VERSION 5.8 ;
BUSBITCHARS "[]" ;
DIVIDERCHAR "/" ;
UNITS
    DATABASE MICRONS 1000 ;
END UNITS

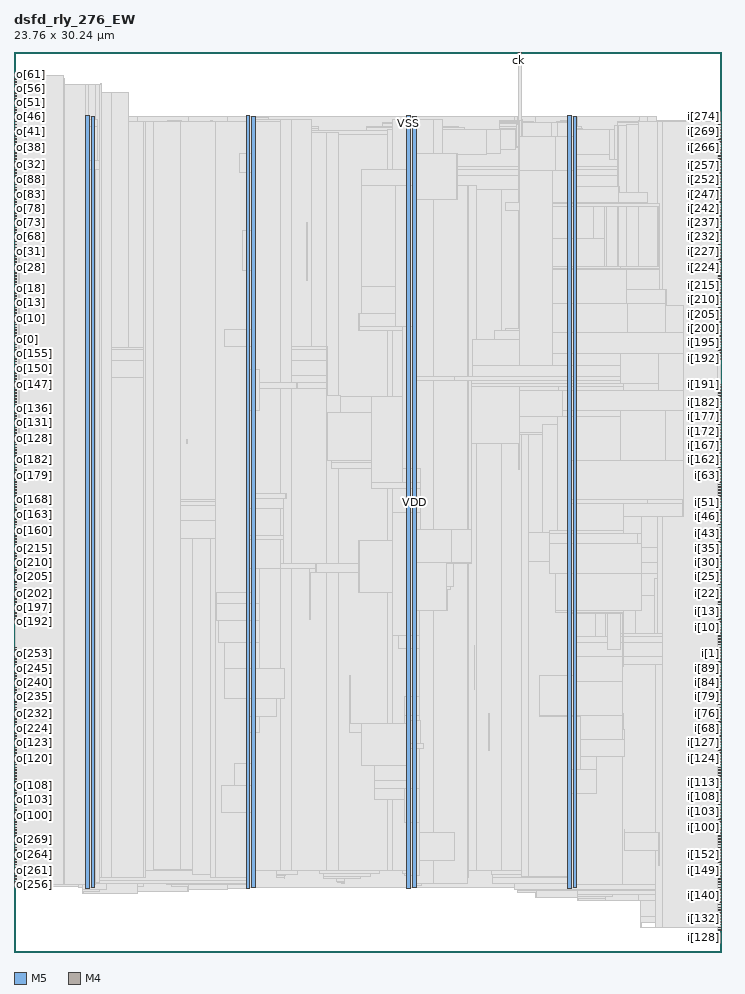
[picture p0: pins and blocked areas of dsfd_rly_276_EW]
MACRO dsfd_rly_276_EW
  FOREIGN dsfd_rly_276_EW 0 0 ;
  CLASS BLOCK ;
  SIZE 23.76 BY 30.24 ;
  PIN ck
    DIRECTION INPUT ;
    USE SIGNAL ;
    PORT
      LAYER M5 ;
        RECT  16.944 30.156 16.968 30.24 ;
    END
  END ck
  PIN i[0]
    DIRECTION INPUT ;
    USE SIGNAL ;
    PORT
      LAYER M4 ;
        RECT  23.676 9.936 23.76 9.96 ;
    END
  END i[0]
  PIN i[100]
    DIRECTION INPUT ;
    USE SIGNAL ;
    PORT
      LAYER M4 ;
        RECT  23.676 4.176 23.76 4.2 ;
    END
  END i[100]
  PIN i[101]
    DIRECTION INPUT ;
    USE SIGNAL ;
    PORT
      LAYER M4 ;
        RECT  23.676 4.272 23.76 4.296 ;
    END
  END i[101]
  PIN i[102]
    DIRECTION INPUT ;
    USE SIGNAL ;
    PORT
      LAYER M4 ;
        RECT  23.676 4.368 23.76 4.392 ;
    END
  END i[102]
  PIN i[103]
    DIRECTION INPUT ;
    USE SIGNAL ;
    PORT
      LAYER M4 ;
        RECT  23.676 4.464 23.76 4.488 ;
    END
  END i[103]
  PIN i[104]
    DIRECTION INPUT ;
    USE SIGNAL ;
    PORT
      LAYER M4 ;
        RECT  23.676 4.56 23.76 4.584 ;
    END
  END i[104]
  PIN i[105]
    DIRECTION INPUT ;
    USE SIGNAL ;
    PORT
      LAYER M4 ;
        RECT  23.676 4.656 23.76 4.68 ;
    END
  END i[105]
  PIN i[106]
    DIRECTION INPUT ;
    USE SIGNAL ;
    PORT
      LAYER M4 ;
        RECT  23.676 4.752 23.76 4.776 ;
    END
  END i[106]
  PIN i[107]
    DIRECTION INPUT ;
    USE SIGNAL ;
    PORT
      LAYER M4 ;
        RECT  23.676 4.848 23.76 4.872 ;
    END
  END i[107]
  PIN i[108]
    DIRECTION INPUT ;
    USE SIGNAL ;
    PORT
      LAYER M4 ;
        RECT  23.676 4.944 23.76 4.968 ;
    END
  END i[108]
  PIN i[109]
    DIRECTION INPUT ;
    USE SIGNAL ;
    PORT
      LAYER M4 ;
        RECT  23.676 5.04 23.76 5.064 ;
    END
  END i[109]
  PIN i[10]
    DIRECTION INPUT ;
    USE SIGNAL ;
    PORT
      LAYER M4 ;
        RECT  23.676 10.896 23.76 10.92 ;
    END
  END i[10]
  PIN i[110]
    DIRECTION INPUT ;
    USE SIGNAL ;
    PORT
      LAYER M4 ;
        RECT  23.676 5.136 23.76 5.16 ;
    END
  END i[110]
  PIN i[111]
    DIRECTION INPUT ;
    USE SIGNAL ;
    PORT
      LAYER M4 ;
        RECT  23.676 5.232 23.76 5.256 ;
    END
  END i[111]
  PIN i[112]
    DIRECTION INPUT ;
    USE SIGNAL ;
    PORT
      LAYER M4 ;
        RECT  23.676 5.328 23.76 5.352 ;
    END
  END i[112]
  PIN i[113]
    DIRECTION INPUT ;
    USE SIGNAL ;
    PORT
      LAYER M4 ;
        RECT  23.676 5.424 23.76 5.448 ;
    END
  END i[113]
  PIN i[114]
    DIRECTION INPUT ;
    USE SIGNAL ;
    PORT
      LAYER M4 ;
        RECT  23.676 5.52 23.76 5.544 ;
    END
  END i[114]
  PIN i[115]
    DIRECTION INPUT ;
    USE SIGNAL ;
    PORT
      LAYER M4 ;
        RECT  23.676 5.616 23.76 5.64 ;
    END
  END i[115]
  PIN i[116]
    DIRECTION INPUT ;
    USE SIGNAL ;
    PORT
      LAYER M4 ;
        RECT  23.676 5.712 23.76 5.736 ;
    END
  END i[116]
  PIN i[117]
    DIRECTION INPUT ;
    USE SIGNAL ;
    PORT
      LAYER M4 ;
        RECT  23.676 5.808 23.76 5.832 ;
    END
  END i[117]
  PIN i[118]
    DIRECTION INPUT ;
    USE SIGNAL ;
    PORT
      LAYER M4 ;
        RECT  23.676 5.904 23.76 5.928 ;
    END
  END i[118]
  PIN i[119]
    DIRECTION INPUT ;
    USE SIGNAL ;
    PORT
      LAYER M4 ;
        RECT  23.676 6 23.76 6.024 ;
    END
  END i[119]
  PIN i[11]
    DIRECTION INPUT ;
    USE SIGNAL ;
    PORT
      LAYER M4 ;
        RECT  23.676 10.992 23.76 11.016 ;
    END
  END i[11]
  PIN i[120]
    DIRECTION INPUT ;
    USE SIGNAL ;
    PORT
      LAYER M4 ;
        RECT  23.676 6.096 23.76 6.12 ;
    END
  END i[120]
  PIN i[121]
    DIRECTION INPUT ;
    USE SIGNAL ;
    PORT
      LAYER M4 ;
        RECT  23.676 6.192 23.76 6.216 ;
    END
  END i[121]
  PIN i[122]
    DIRECTION INPUT ;
    USE SIGNAL ;
    PORT
      LAYER M4 ;
        RECT  23.676 6.288 23.76 6.312 ;
    END
  END i[122]
  PIN i[123]
    DIRECTION INPUT ;
    USE SIGNAL ;
    PORT
      LAYER M4 ;
        RECT  23.676 6.384 23.76 6.408 ;
    END
  END i[123]
  PIN i[124]
    DIRECTION INPUT ;
    USE SIGNAL ;
    PORT
      LAYER M4 ;
        RECT  23.676 6.48 23.76 6.504 ;
    END
  END i[124]
  PIN i[125]
    DIRECTION INPUT ;
    USE SIGNAL ;
    PORT
      LAYER M4 ;
        RECT  23.676 6.576 23.76 6.6 ;
    END
  END i[125]
  PIN i[126]
    DIRECTION INPUT ;
    USE SIGNAL ;
    PORT
      LAYER M4 ;
        RECT  23.676 6.672 23.76 6.696 ;
    END
  END i[126]
  PIN i[127]
    DIRECTION INPUT ;
    USE SIGNAL ;
    PORT
      LAYER M4 ;
        RECT  23.676 6.768 23.76 6.792 ;
    END
  END i[127]
  PIN i[128]
    DIRECTION INPUT ;
    USE SIGNAL ;
    PORT
      LAYER M4 ;
        RECT  23.676 0.72 23.76 0.744 ;
    END
  END i[128]
  PIN i[129]
    DIRECTION INPUT ;
    USE SIGNAL ;
    PORT
      LAYER M4 ;
        RECT  23.676 0.816 23.76 0.84 ;
    END
  END i[129]
  PIN i[12]
    DIRECTION INPUT ;
    USE SIGNAL ;
    PORT
      LAYER M4 ;
        RECT  23.676 11.088 23.76 11.112 ;
    END
  END i[12]
  PIN i[130]
    DIRECTION INPUT ;
    USE SIGNAL ;
    PORT
      LAYER M4 ;
        RECT  23.676 0.912 23.76 0.936 ;
    END
  END i[130]
  PIN i[131]
    DIRECTION INPUT ;
    USE SIGNAL ;
    PORT
      LAYER M4 ;
        RECT  23.676 1.008 23.76 1.032 ;
    END
  END i[131]
  PIN i[132]
    DIRECTION INPUT ;
    USE SIGNAL ;
    PORT
      LAYER M4 ;
        RECT  23.676 1.104 23.76 1.128 ;
    END
  END i[132]
  PIN i[133]
    DIRECTION INPUT ;
    USE SIGNAL ;
    PORT
      LAYER M4 ;
        RECT  23.676 1.2 23.76 1.224 ;
    END
  END i[133]
  PIN i[134]
    DIRECTION INPUT ;
    USE SIGNAL ;
    PORT
      LAYER M4 ;
        RECT  23.676 1.296 23.76 1.32 ;
    END
  END i[134]
  PIN i[135]
    DIRECTION INPUT ;
    USE SIGNAL ;
    PORT
      LAYER M4 ;
        RECT  23.676 1.392 23.76 1.416 ;
    END
  END i[135]
  PIN i[136]
    DIRECTION INPUT ;
    USE SIGNAL ;
    PORT
      LAYER M4 ;
        RECT  23.676 1.488 23.76 1.512 ;
    END
  END i[136]
  PIN i[137]
    DIRECTION INPUT ;
    USE SIGNAL ;
    PORT
      LAYER M4 ;
        RECT  23.676 1.584 23.76 1.608 ;
    END
  END i[137]
  PIN i[138]
    DIRECTION INPUT ;
    USE SIGNAL ;
    PORT
      LAYER M4 ;
        RECT  23.676 1.68 23.76 1.704 ;
    END
  END i[138]
  PIN i[139]
    DIRECTION INPUT ;
    USE SIGNAL ;
    PORT
      LAYER M4 ;
        RECT  23.676 1.776 23.76 1.8 ;
    END
  END i[139]
  PIN i[13]
    DIRECTION INPUT ;
    USE SIGNAL ;
    PORT
      LAYER M4 ;
        RECT  23.676 11.184 23.76 11.208 ;
    END
  END i[13]
  PIN i[140]
    DIRECTION INPUT ;
    USE SIGNAL ;
    PORT
      LAYER M4 ;
        RECT  23.676 1.872 23.76 1.896 ;
    END
  END i[140]
  PIN i[141]
    DIRECTION INPUT ;
    USE SIGNAL ;
    PORT
      LAYER M4 ;
        RECT  23.676 1.968 23.76 1.992 ;
    END
  END i[141]
  PIN i[142]
    DIRECTION INPUT ;
    USE SIGNAL ;
    PORT
      LAYER M4 ;
        RECT  23.676 2.064 23.76 2.088 ;
    END
  END i[142]
  PIN i[143]
    DIRECTION INPUT ;
    USE SIGNAL ;
    PORT
      LAYER M4 ;
        RECT  23.676 2.16 23.76 2.184 ;
    END
  END i[143]
  PIN i[144]
    DIRECTION INPUT ;
    USE SIGNAL ;
    PORT
      LAYER M4 ;
        RECT  23.676 2.256 23.76 2.28 ;
    END
  END i[144]
  PIN i[145]
    DIRECTION INPUT ;
    USE SIGNAL ;
    PORT
      LAYER M4 ;
        RECT  23.676 2.352 23.76 2.376 ;
    END
  END i[145]
  PIN i[146]
    DIRECTION INPUT ;
    USE SIGNAL ;
    PORT
      LAYER M4 ;
        RECT  23.676 2.448 23.76 2.472 ;
    END
  END i[146]
  PIN i[147]
    DIRECTION INPUT ;
    USE SIGNAL ;
    PORT
      LAYER M4 ;
        RECT  23.676 2.544 23.76 2.568 ;
    END
  END i[147]
  PIN i[148]
    DIRECTION INPUT ;
    USE SIGNAL ;
    PORT
      LAYER M4 ;
        RECT  23.676 2.64 23.76 2.664 ;
    END
  END i[148]
  PIN i[149]
    DIRECTION INPUT ;
    USE SIGNAL ;
    PORT
      LAYER M4 ;
        RECT  23.676 2.736 23.76 2.76 ;
    END
  END i[149]
  PIN i[14]
    DIRECTION INPUT ;
    USE SIGNAL ;
    PORT
      LAYER M4 ;
        RECT  23.676 11.28 23.76 11.304 ;
    END
  END i[14]
  PIN i[150]
    DIRECTION INPUT ;
    USE SIGNAL ;
    PORT
      LAYER M4 ;
        RECT  23.676 2.832 23.76 2.856 ;
    END
  END i[150]
  PIN i[151]
    DIRECTION INPUT ;
    USE SIGNAL ;
    PORT
      LAYER M4 ;
        RECT  23.676 2.928 23.76 2.952 ;
    END
  END i[151]
  PIN i[152]
    DIRECTION INPUT ;
    USE SIGNAL ;
    PORT
      LAYER M4 ;
        RECT  23.676 3.024 23.76 3.048 ;
    END
  END i[152]
  PIN i[153]
    DIRECTION INPUT ;
    USE SIGNAL ;
    PORT
      LAYER M4 ;
        RECT  23.676 3.12 23.76 3.144 ;
    END
  END i[153]
  PIN i[154]
    DIRECTION INPUT ;
    USE SIGNAL ;
    PORT
      LAYER M4 ;
        RECT  23.676 3.216 23.76 3.24 ;
    END
  END i[154]
  PIN i[155]
    DIRECTION INPUT ;
    USE SIGNAL ;
    PORT
      LAYER M4 ;
        RECT  23.676 3.312 23.76 3.336 ;
    END
  END i[155]
  PIN i[156]
    DIRECTION INPUT ;
    USE SIGNAL ;
    PORT
      LAYER M4 ;
        RECT  23.676 3.408 23.76 3.432 ;
    END
  END i[156]
  PIN i[157]
    DIRECTION INPUT ;
    USE SIGNAL ;
    PORT
      LAYER M4 ;
        RECT  23.676 3.504 23.76 3.528 ;
    END
  END i[157]
  PIN i[158]
    DIRECTION INPUT ;
    USE SIGNAL ;
    PORT
      LAYER M4 ;
        RECT  23.676 3.6 23.76 3.624 ;
    END
  END i[158]
  PIN i[159]
    DIRECTION INPUT ;
    USE SIGNAL ;
    PORT
      LAYER M4 ;
        RECT  23.676 3.696 23.76 3.72 ;
    END
  END i[159]
  PIN i[15]
    DIRECTION INPUT ;
    USE SIGNAL ;
    PORT
      LAYER M4 ;
        RECT  23.676 11.376 23.76 11.4 ;
    END
  END i[15]
  PIN i[160]
    DIRECTION INPUT ;
    USE SIGNAL ;
    PORT
      LAYER M4 ;
        RECT  23.676 16.08 23.76 16.104 ;
    END
  END i[160]
  PIN i[161]
    DIRECTION INPUT ;
    USE SIGNAL ;
    PORT
      LAYER M4 ;
        RECT  23.676 16.176 23.76 16.2 ;
    END
  END i[161]
  PIN i[162]
    DIRECTION INPUT ;
    USE SIGNAL ;
    PORT
      LAYER M4 ;
        RECT  23.676 16.272 23.76 16.296 ;
    END
  END i[162]
  PIN i[163]
    DIRECTION INPUT ;
    USE SIGNAL ;
    PORT
      LAYER M4 ;
        RECT  23.676 16.368 23.76 16.392 ;
    END
  END i[163]
  PIN i[164]
    DIRECTION INPUT ;
    USE SIGNAL ;
    PORT
      LAYER M4 ;
        RECT  23.676 16.464 23.76 16.488 ;
    END
  END i[164]
  PIN i[165]
    DIRECTION INPUT ;
    USE SIGNAL ;
    PORT
      LAYER M4 ;
        RECT  23.676 16.56 23.76 16.584 ;
    END
  END i[165]
  PIN i[166]
    DIRECTION INPUT ;
    USE SIGNAL ;
    PORT
      LAYER M4 ;
        RECT  23.676 16.656 23.76 16.68 ;
    END
  END i[166]
  PIN i[167]
    DIRECTION INPUT ;
    USE SIGNAL ;
    PORT
      LAYER M4 ;
        RECT  23.676 16.752 23.76 16.776 ;
    END
  END i[167]
  PIN i[168]
    DIRECTION INPUT ;
    USE SIGNAL ;
    PORT
      LAYER M4 ;
        RECT  23.676 16.848 23.76 16.872 ;
    END
  END i[168]
  PIN i[169]
    DIRECTION INPUT ;
    USE SIGNAL ;
    PORT
      LAYER M4 ;
        RECT  23.676 16.944 23.76 16.968 ;
    END
  END i[169]
  PIN i[16]
    DIRECTION INPUT ;
    USE SIGNAL ;
    PORT
      LAYER M4 ;
        RECT  23.676 11.472 23.76 11.496 ;
    END
  END i[16]
  PIN i[170]
    DIRECTION INPUT ;
    USE SIGNAL ;
    PORT
      LAYER M4 ;
        RECT  23.676 17.04 23.76 17.064 ;
    END
  END i[170]
  PIN i[171]
    DIRECTION INPUT ;
    USE SIGNAL ;
    PORT
      LAYER M4 ;
        RECT  23.676 17.136 23.76 17.16 ;
    END
  END i[171]
  PIN i[172]
    DIRECTION INPUT ;
    USE SIGNAL ;
    PORT
      LAYER M4 ;
        RECT  23.676 17.232 23.76 17.256 ;
    END
  END i[172]
  PIN i[173]
    DIRECTION INPUT ;
    USE SIGNAL ;
    PORT
      LAYER M4 ;
        RECT  23.676 17.328 23.76 17.352 ;
    END
  END i[173]
  PIN i[174]
    DIRECTION INPUT ;
    USE SIGNAL ;
    PORT
      LAYER M4 ;
        RECT  23.676 17.424 23.76 17.448 ;
    END
  END i[174]
  PIN i[175]
    DIRECTION INPUT ;
    USE SIGNAL ;
    PORT
      LAYER M4 ;
        RECT  23.676 17.52 23.76 17.544 ;
    END
  END i[175]
  PIN i[176]
    DIRECTION INPUT ;
    USE SIGNAL ;
    PORT
      LAYER M4 ;
        RECT  23.676 17.616 23.76 17.64 ;
    END
  END i[176]
  PIN i[177]
    DIRECTION INPUT ;
    USE SIGNAL ;
    PORT
      LAYER M4 ;
        RECT  23.676 17.712 23.76 17.736 ;
    END
  END i[177]
  PIN i[178]
    DIRECTION INPUT ;
    USE SIGNAL ;
    PORT
      LAYER M4 ;
        RECT  23.676 17.808 23.76 17.832 ;
    END
  END i[178]
  PIN i[179]
    DIRECTION INPUT ;
    USE SIGNAL ;
    PORT
      LAYER M4 ;
        RECT  23.676 17.904 23.76 17.928 ;
    END
  END i[179]
  PIN i[17]
    DIRECTION INPUT ;
    USE SIGNAL ;
    PORT
      LAYER M4 ;
        RECT  23.676 11.568 23.76 11.592 ;
    END
  END i[17]
  PIN i[180]
    DIRECTION INPUT ;
    USE SIGNAL ;
    PORT
      LAYER M4 ;
        RECT  23.676 18 23.76 18.024 ;
    END
  END i[180]
  PIN i[181]
    DIRECTION INPUT ;
    USE SIGNAL ;
    PORT
      LAYER M4 ;
        RECT  23.676 18.096 23.76 18.12 ;
    END
  END i[181]
  PIN i[182]
    DIRECTION INPUT ;
    USE SIGNAL ;
    PORT
      LAYER M4 ;
        RECT  23.676 18.192 23.76 18.216 ;
    END
  END i[182]
  PIN i[183]
    DIRECTION INPUT ;
    USE SIGNAL ;
    PORT
      LAYER M4 ;
        RECT  23.676 18.288 23.76 18.312 ;
    END
  END i[183]
  PIN i[184]
    DIRECTION INPUT ;
    USE SIGNAL ;
    PORT
      LAYER M4 ;
        RECT  23.676 18.384 23.76 18.408 ;
    END
  END i[184]
  PIN i[185]
    DIRECTION INPUT ;
    USE SIGNAL ;
    PORT
      LAYER M4 ;
        RECT  23.676 18.48 23.76 18.504 ;
    END
  END i[185]
  PIN i[186]
    DIRECTION INPUT ;
    USE SIGNAL ;
    PORT
      LAYER M4 ;
        RECT  23.676 18.576 23.76 18.6 ;
    END
  END i[186]
  PIN i[187]
    DIRECTION INPUT ;
    USE SIGNAL ;
    PORT
      LAYER M4 ;
        RECT  23.676 18.672 23.76 18.696 ;
    END
  END i[187]
  PIN i[188]
    DIRECTION INPUT ;
    USE SIGNAL ;
    PORT
      LAYER M4 ;
        RECT  23.676 18.768 23.76 18.792 ;
    END
  END i[188]
  PIN i[189]
    DIRECTION INPUT ;
    USE SIGNAL ;
    PORT
      LAYER M4 ;
        RECT  23.676 18.864 23.76 18.888 ;
    END
  END i[189]
  PIN i[18]
    DIRECTION INPUT ;
    USE SIGNAL ;
    PORT
      LAYER M4 ;
        RECT  23.676 11.664 23.76 11.688 ;
    END
  END i[18]
  PIN i[190]
    DIRECTION INPUT ;
    USE SIGNAL ;
    PORT
      LAYER M4 ;
        RECT  23.676 18.96 23.76 18.984 ;
    END
  END i[190]
  PIN i[191]
    DIRECTION INPUT ;
    USE SIGNAL ;
    PORT
      LAYER M4 ;
        RECT  23.676 19.056 23.76 19.08 ;
    END
  END i[191]
  PIN i[192]
    DIRECTION INPUT ;
    USE SIGNAL ;
    PORT
      LAYER M4 ;
        RECT  23.676 19.92 23.76 19.944 ;
    END
  END i[192]
  PIN i[193]
    DIRECTION INPUT ;
    USE SIGNAL ;
    PORT
      LAYER M4 ;
        RECT  23.676 20.016 23.76 20.04 ;
    END
  END i[193]
  PIN i[194]
    DIRECTION INPUT ;
    USE SIGNAL ;
    PORT
      LAYER M4 ;
        RECT  23.676 20.112 23.76 20.136 ;
    END
  END i[194]
  PIN i[195]
    DIRECTION INPUT ;
    USE SIGNAL ;
    PORT
      LAYER M4 ;
        RECT  23.676 20.208 23.76 20.232 ;
    END
  END i[195]
  PIN i[196]
    DIRECTION INPUT ;
    USE SIGNAL ;
    PORT
      LAYER M4 ;
        RECT  23.676 20.304 23.76 20.328 ;
    END
  END i[196]
  PIN i[197]
    DIRECTION INPUT ;
    USE SIGNAL ;
    PORT
      LAYER M4 ;
        RECT  23.676 20.4 23.76 20.424 ;
    END
  END i[197]
  PIN i[198]
    DIRECTION INPUT ;
    USE SIGNAL ;
    PORT
      LAYER M4 ;
        RECT  23.676 20.496 23.76 20.52 ;
    END
  END i[198]
  PIN i[199]
    DIRECTION INPUT ;
    USE SIGNAL ;
    PORT
      LAYER M4 ;
        RECT  23.676 20.592 23.76 20.616 ;
    END
  END i[199]
  PIN i[19]
    DIRECTION INPUT ;
    USE SIGNAL ;
    PORT
      LAYER M4 ;
        RECT  23.676 11.76 23.76 11.784 ;
    END
  END i[19]
  PIN i[1]
    DIRECTION INPUT ;
    USE SIGNAL ;
    PORT
      LAYER M4 ;
        RECT  23.676 10.032 23.76 10.056 ;
    END
  END i[1]
  PIN i[200]
    DIRECTION INPUT ;
    USE SIGNAL ;
    PORT
      LAYER M4 ;
        RECT  23.676 20.688 23.76 20.712 ;
    END
  END i[200]
  PIN i[201]
    DIRECTION INPUT ;
    USE SIGNAL ;
    PORT
      LAYER M4 ;
        RECT  23.676 20.784 23.76 20.808 ;
    END
  END i[201]
  PIN i[202]
    DIRECTION INPUT ;
    USE SIGNAL ;
    PORT
      LAYER M4 ;
        RECT  23.676 20.88 23.76 20.904 ;
    END
  END i[202]
  PIN i[203]
    DIRECTION INPUT ;
    USE SIGNAL ;
    PORT
      LAYER M4 ;
        RECT  23.676 20.976 23.76 21 ;
    END
  END i[203]
  PIN i[204]
    DIRECTION INPUT ;
    USE SIGNAL ;
    PORT
      LAYER M4 ;
        RECT  23.676 21.072 23.76 21.096 ;
    END
  END i[204]
  PIN i[205]
    DIRECTION INPUT ;
    USE SIGNAL ;
    PORT
      LAYER M4 ;
        RECT  23.676 21.168 23.76 21.192 ;
    END
  END i[205]
  PIN i[206]
    DIRECTION INPUT ;
    USE SIGNAL ;
    PORT
      LAYER M4 ;
        RECT  23.676 21.264 23.76 21.288 ;
    END
  END i[206]
  PIN i[207]
    DIRECTION INPUT ;
    USE SIGNAL ;
    PORT
      LAYER M4 ;
        RECT  23.676 21.36 23.76 21.384 ;
    END
  END i[207]
  PIN i[208]
    DIRECTION INPUT ;
    USE SIGNAL ;
    PORT
      LAYER M4 ;
        RECT  23.676 21.456 23.76 21.48 ;
    END
  END i[208]
  PIN i[209]
    DIRECTION INPUT ;
    USE SIGNAL ;
    PORT
      LAYER M4 ;
        RECT  23.676 21.552 23.76 21.576 ;
    END
  END i[209]
  PIN i[20]
    DIRECTION INPUT ;
    USE SIGNAL ;
    PORT
      LAYER M4 ;
        RECT  23.676 11.856 23.76 11.88 ;
    END
  END i[20]
  PIN i[210]
    DIRECTION INPUT ;
    USE SIGNAL ;
    PORT
      LAYER M4 ;
        RECT  23.676 21.648 23.76 21.672 ;
    END
  END i[210]
  PIN i[211]
    DIRECTION INPUT ;
    USE SIGNAL ;
    PORT
      LAYER M4 ;
        RECT  23.676 21.744 23.76 21.768 ;
    END
  END i[211]
  PIN i[212]
    DIRECTION INPUT ;
    USE SIGNAL ;
    PORT
      LAYER M4 ;
        RECT  23.676 21.84 23.76 21.864 ;
    END
  END i[212]
  PIN i[213]
    DIRECTION INPUT ;
    USE SIGNAL ;
    PORT
      LAYER M4 ;
        RECT  23.676 21.936 23.76 21.96 ;
    END
  END i[213]
  PIN i[214]
    DIRECTION INPUT ;
    USE SIGNAL ;
    PORT
      LAYER M4 ;
        RECT  23.676 22.032 23.76 22.056 ;
    END
  END i[214]
  PIN i[215]
    DIRECTION INPUT ;
    USE SIGNAL ;
    PORT
      LAYER M4 ;
        RECT  23.676 22.128 23.76 22.152 ;
    END
  END i[215]
  PIN i[216]
    DIRECTION INPUT ;
    USE SIGNAL ;
    PORT
      LAYER M4 ;
        RECT  23.676 22.224 23.76 22.248 ;
    END
  END i[216]
  PIN i[217]
    DIRECTION INPUT ;
    USE SIGNAL ;
    PORT
      LAYER M4 ;
        RECT  23.676 22.32 23.76 22.344 ;
    END
  END i[217]
  PIN i[218]
    DIRECTION INPUT ;
    USE SIGNAL ;
    PORT
      LAYER M4 ;
        RECT  23.676 22.416 23.76 22.44 ;
    END
  END i[218]
  PIN i[219]
    DIRECTION INPUT ;
    USE SIGNAL ;
    PORT
      LAYER M4 ;
        RECT  23.676 22.512 23.76 22.536 ;
    END
  END i[219]
  PIN i[21]
    DIRECTION INPUT ;
    USE SIGNAL ;
    PORT
      LAYER M4 ;
        RECT  23.676 11.952 23.76 11.976 ;
    END
  END i[21]
  PIN i[220]
    DIRECTION INPUT ;
    USE SIGNAL ;
    PORT
      LAYER M4 ;
        RECT  23.676 22.608 23.76 22.632 ;
    END
  END i[220]
  PIN i[221]
    DIRECTION INPUT ;
    USE SIGNAL ;
    PORT
      LAYER M4 ;
        RECT  23.676 22.704 23.76 22.728 ;
    END
  END i[221]
  PIN i[222]
    DIRECTION INPUT ;
    USE SIGNAL ;
    PORT
      LAYER M4 ;
        RECT  23.676 22.8 23.76 22.824 ;
    END
  END i[222]
  PIN i[223]
    DIRECTION INPUT ;
    USE SIGNAL ;
    PORT
      LAYER M4 ;
        RECT  23.676 22.896 23.76 22.92 ;
    END
  END i[223]
  PIN i[224]
    DIRECTION INPUT ;
    USE SIGNAL ;
    PORT
      LAYER M4 ;
        RECT  23.676 22.992 23.76 23.016 ;
    END
  END i[224]
  PIN i[225]
    DIRECTION INPUT ;
    USE SIGNAL ;
    PORT
      LAYER M4 ;
        RECT  23.676 23.088 23.76 23.112 ;
    END
  END i[225]
  PIN i[226]
    DIRECTION INPUT ;
    USE SIGNAL ;
    PORT
      LAYER M4 ;
        RECT  23.676 23.184 23.76 23.208 ;
    END
  END i[226]
  PIN i[227]
    DIRECTION INPUT ;
    USE SIGNAL ;
    PORT
      LAYER M4 ;
        RECT  23.676 23.28 23.76 23.304 ;
    END
  END i[227]
  PIN i[228]
    DIRECTION INPUT ;
    USE SIGNAL ;
    PORT
      LAYER M4 ;
        RECT  23.676 23.376 23.76 23.4 ;
    END
  END i[228]
  PIN i[229]
    DIRECTION INPUT ;
    USE SIGNAL ;
    PORT
      LAYER M4 ;
        RECT  23.676 23.472 23.76 23.496 ;
    END
  END i[229]
  PIN i[22]
    DIRECTION INPUT ;
    USE SIGNAL ;
    PORT
      LAYER M4 ;
        RECT  23.676 12.048 23.76 12.072 ;
    END
  END i[22]
  PIN i[230]
    DIRECTION INPUT ;
    USE SIGNAL ;
    PORT
      LAYER M4 ;
        RECT  23.676 23.568 23.76 23.592 ;
    END
  END i[230]
  PIN i[231]
    DIRECTION INPUT ;
    USE SIGNAL ;
    PORT
      LAYER M4 ;
        RECT  23.676 23.664 23.76 23.688 ;
    END
  END i[231]
  PIN i[232]
    DIRECTION INPUT ;
    USE SIGNAL ;
    PORT
      LAYER M4 ;
        RECT  23.676 23.76 23.76 23.784 ;
    END
  END i[232]
  PIN i[233]
    DIRECTION INPUT ;
    USE SIGNAL ;
    PORT
      LAYER M4 ;
        RECT  23.676 23.856 23.76 23.88 ;
    END
  END i[233]
  PIN i[234]
    DIRECTION INPUT ;
    USE SIGNAL ;
    PORT
      LAYER M4 ;
        RECT  23.676 23.952 23.76 23.976 ;
    END
  END i[234]
  PIN i[235]
    DIRECTION INPUT ;
    USE SIGNAL ;
    PORT
      LAYER M4 ;
        RECT  23.676 24.048 23.76 24.072 ;
    END
  END i[235]
  PIN i[236]
    DIRECTION INPUT ;
    USE SIGNAL ;
    PORT
      LAYER M4 ;
        RECT  23.676 24.144 23.76 24.168 ;
    END
  END i[236]
  PIN i[237]
    DIRECTION INPUT ;
    USE SIGNAL ;
    PORT
      LAYER M4 ;
        RECT  23.676 24.24 23.76 24.264 ;
    END
  END i[237]
  PIN i[238]
    DIRECTION INPUT ;
    USE SIGNAL ;
    PORT
      LAYER M4 ;
        RECT  23.676 24.336 23.76 24.36 ;
    END
  END i[238]
  PIN i[239]
    DIRECTION INPUT ;
    USE SIGNAL ;
    PORT
      LAYER M4 ;
        RECT  23.676 24.432 23.76 24.456 ;
    END
  END i[239]
  PIN i[23]
    DIRECTION INPUT ;
    USE SIGNAL ;
    PORT
      LAYER M4 ;
        RECT  23.676 12.144 23.76 12.168 ;
    END
  END i[23]
  PIN i[240]
    DIRECTION INPUT ;
    USE SIGNAL ;
    PORT
      LAYER M4 ;
        RECT  23.676 24.528 23.76 24.552 ;
    END
  END i[240]
  PIN i[241]
    DIRECTION INPUT ;
    USE SIGNAL ;
    PORT
      LAYER M4 ;
        RECT  23.676 24.624 23.76 24.648 ;
    END
  END i[241]
  PIN i[242]
    DIRECTION INPUT ;
    USE SIGNAL ;
    PORT
      LAYER M4 ;
        RECT  23.676 24.72 23.76 24.744 ;
    END
  END i[242]
  PIN i[243]
    DIRECTION INPUT ;
    USE SIGNAL ;
    PORT
      LAYER M4 ;
        RECT  23.676 24.816 23.76 24.84 ;
    END
  END i[243]
  PIN i[244]
    DIRECTION INPUT ;
    USE SIGNAL ;
    PORT
      LAYER M4 ;
        RECT  23.676 24.912 23.76 24.936 ;
    END
  END i[244]
  PIN i[245]
    DIRECTION INPUT ;
    USE SIGNAL ;
    PORT
      LAYER M4 ;
        RECT  23.676 25.008 23.76 25.032 ;
    END
  END i[245]
  PIN i[246]
    DIRECTION INPUT ;
    USE SIGNAL ;
    PORT
      LAYER M4 ;
        RECT  23.676 25.104 23.76 25.128 ;
    END
  END i[246]
  PIN i[247]
    DIRECTION INPUT ;
    USE SIGNAL ;
    PORT
      LAYER M4 ;
        RECT  23.676 25.2 23.76 25.224 ;
    END
  END i[247]
  PIN i[248]
    DIRECTION INPUT ;
    USE SIGNAL ;
    PORT
      LAYER M4 ;
        RECT  23.676 25.296 23.76 25.32 ;
    END
  END i[248]
  PIN i[249]
    DIRECTION INPUT ;
    USE SIGNAL ;
    PORT
      LAYER M4 ;
        RECT  23.676 25.392 23.76 25.416 ;
    END
  END i[249]
  PIN i[24]
    DIRECTION INPUT ;
    USE SIGNAL ;
    PORT
      LAYER M4 ;
        RECT  23.676 12.24 23.76 12.264 ;
    END
  END i[24]
  PIN i[250]
    DIRECTION INPUT ;
    USE SIGNAL ;
    PORT
      LAYER M4 ;
        RECT  23.676 25.488 23.76 25.512 ;
    END
  END i[250]
  PIN i[251]
    DIRECTION INPUT ;
    USE SIGNAL ;
    PORT
      LAYER M4 ;
        RECT  23.676 25.584 23.76 25.608 ;
    END
  END i[251]
  PIN i[252]
    DIRECTION INPUT ;
    USE SIGNAL ;
    PORT
      LAYER M4 ;
        RECT  23.676 25.68 23.76 25.704 ;
    END
  END i[252]
  PIN i[253]
    DIRECTION INPUT ;
    USE SIGNAL ;
    PORT
      LAYER M4 ;
        RECT  23.676 25.776 23.76 25.8 ;
    END
  END i[253]
  PIN i[254]
    DIRECTION INPUT ;
    USE SIGNAL ;
    PORT
      LAYER M4 ;
        RECT  23.676 25.872 23.76 25.896 ;
    END
  END i[254]
  PIN i[255]
    DIRECTION INPUT ;
    USE SIGNAL ;
    PORT
      LAYER M4 ;
        RECT  23.676 25.968 23.76 25.992 ;
    END
  END i[255]
  PIN i[256]
    DIRECTION INPUT ;
    USE SIGNAL ;
    PORT
      LAYER M4 ;
        RECT  23.676 26.064 23.76 26.088 ;
    END
  END i[256]
  PIN i[257]
    DIRECTION INPUT ;
    USE SIGNAL ;
    PORT
      LAYER M4 ;
        RECT  23.676 26.16 23.76 26.184 ;
    END
  END i[257]
  PIN i[258]
    DIRECTION INPUT ;
    USE SIGNAL ;
    PORT
      LAYER M4 ;
        RECT  23.676 26.256 23.76 26.28 ;
    END
  END i[258]
  PIN i[259]
    DIRECTION INPUT ;
    USE SIGNAL ;
    PORT
      LAYER M4 ;
        RECT  23.676 26.352 23.76 26.376 ;
    END
  END i[259]
  PIN i[25]
    DIRECTION INPUT ;
    USE SIGNAL ;
    PORT
      LAYER M4 ;
        RECT  23.676 12.336 23.76 12.36 ;
    END
  END i[25]
  PIN i[260]
    DIRECTION INPUT ;
    USE SIGNAL ;
    PORT
      LAYER M4 ;
        RECT  23.676 26.448 23.76 26.472 ;
    END
  END i[260]
  PIN i[261]
    DIRECTION INPUT ;
    USE SIGNAL ;
    PORT
      LAYER M4 ;
        RECT  23.676 26.544 23.76 26.568 ;
    END
  END i[261]
  PIN i[262]
    DIRECTION INPUT ;
    USE SIGNAL ;
    PORT
      LAYER M4 ;
        RECT  23.676 26.64 23.76 26.664 ;
    END
  END i[262]
  PIN i[263]
    DIRECTION INPUT ;
    USE SIGNAL ;
    PORT
      LAYER M4 ;
        RECT  23.676 26.736 23.76 26.76 ;
    END
  END i[263]
  PIN i[264]
    DIRECTION INPUT ;
    USE SIGNAL ;
    PORT
      LAYER M4 ;
        RECT  23.676 26.832 23.76 26.856 ;
    END
  END i[264]
  PIN i[265]
    DIRECTION INPUT ;
    USE SIGNAL ;
    PORT
      LAYER M4 ;
        RECT  23.676 26.928 23.76 26.952 ;
    END
  END i[265]
  PIN i[266]
    DIRECTION INPUT ;
    USE SIGNAL ;
    PORT
      LAYER M4 ;
        RECT  23.676 27.024 23.76 27.048 ;
    END
  END i[266]
  PIN i[267]
    DIRECTION INPUT ;
    USE SIGNAL ;
    PORT
      LAYER M4 ;
        RECT  23.676 27.12 23.76 27.144 ;
    END
  END i[267]
  PIN i[268]
    DIRECTION INPUT ;
    USE SIGNAL ;
    PORT
      LAYER M4 ;
        RECT  23.676 27.216 23.76 27.24 ;
    END
  END i[268]
  PIN i[269]
    DIRECTION INPUT ;
    USE SIGNAL ;
    PORT
      LAYER M4 ;
        RECT  23.676 27.312 23.76 27.336 ;
    END
  END i[269]
  PIN i[26]
    DIRECTION INPUT ;
    USE SIGNAL ;
    PORT
      LAYER M4 ;
        RECT  23.676 12.432 23.76 12.456 ;
    END
  END i[26]
  PIN i[270]
    DIRECTION INPUT ;
    USE SIGNAL ;
    PORT
      LAYER M4 ;
        RECT  23.676 27.408 23.76 27.432 ;
    END
  END i[270]
  PIN i[271]
    DIRECTION INPUT ;
    USE SIGNAL ;
    PORT
      LAYER M4 ;
        RECT  23.676 27.504 23.76 27.528 ;
    END
  END i[271]
  PIN i[272]
    DIRECTION INPUT ;
    USE SIGNAL ;
    PORT
      LAYER M4 ;
        RECT  23.676 27.6 23.76 27.624 ;
    END
  END i[272]
  PIN i[273]
    DIRECTION INPUT ;
    USE SIGNAL ;
    PORT
      LAYER M4 ;
        RECT  23.676 27.696 23.76 27.72 ;
    END
  END i[273]
  PIN i[274]
    DIRECTION INPUT ;
    USE SIGNAL ;
    PORT
      LAYER M4 ;
        RECT  23.676 27.792 23.76 27.816 ;
    END
  END i[274]
  PIN i[275]
    DIRECTION INPUT ;
    USE SIGNAL ;
    PORT
      LAYER M4 ;
        RECT  23.676 27.888 23.76 27.912 ;
    END
  END i[275]
  PIN i[27]
    DIRECTION INPUT ;
    USE SIGNAL ;
    PORT
      LAYER M4 ;
        RECT  23.676 12.528 23.76 12.552 ;
    END
  END i[27]
  PIN i[28]
    DIRECTION INPUT ;
    USE SIGNAL ;
    PORT
      LAYER M4 ;
        RECT  23.676 12.624 23.76 12.648 ;
    END
  END i[28]
  PIN i[29]
    DIRECTION INPUT ;
    USE SIGNAL ;
    PORT
      LAYER M4 ;
        RECT  23.676 12.72 23.76 12.744 ;
    END
  END i[29]
  PIN i[2]
    DIRECTION INPUT ;
    USE SIGNAL ;
    PORT
      LAYER M4 ;
        RECT  23.676 10.128 23.76 10.152 ;
    END
  END i[2]
  PIN i[30]
    DIRECTION INPUT ;
    USE SIGNAL ;
    PORT
      LAYER M4 ;
        RECT  23.676 12.816 23.76 12.84 ;
    END
  END i[30]
  PIN i[31]
    DIRECTION INPUT ;
    USE SIGNAL ;
    PORT
      LAYER M4 ;
        RECT  23.676 12.912 23.76 12.936 ;
    END
  END i[31]
  PIN i[32]
    DIRECTION INPUT ;
    USE SIGNAL ;
    PORT
      LAYER M4 ;
        RECT  23.676 13.008 23.76 13.032 ;
    END
  END i[32]
  PIN i[33]
    DIRECTION INPUT ;
    USE SIGNAL ;
    PORT
      LAYER M4 ;
        RECT  23.676 13.104 23.76 13.128 ;
    END
  END i[33]
  PIN i[34]
    DIRECTION INPUT ;
    USE SIGNAL ;
    PORT
      LAYER M4 ;
        RECT  23.676 13.2 23.76 13.224 ;
    END
  END i[34]
  PIN i[35]
    DIRECTION INPUT ;
    USE SIGNAL ;
    PORT
      LAYER M4 ;
        RECT  23.676 13.296 23.76 13.32 ;
    END
  END i[35]
  PIN i[36]
    DIRECTION INPUT ;
    USE SIGNAL ;
    PORT
      LAYER M4 ;
        RECT  23.676 13.392 23.76 13.416 ;
    END
  END i[36]
  PIN i[37]
    DIRECTION INPUT ;
    USE SIGNAL ;
    PORT
      LAYER M4 ;
        RECT  23.676 13.488 23.76 13.512 ;
    END
  END i[37]
  PIN i[38]
    DIRECTION INPUT ;
    USE SIGNAL ;
    PORT
      LAYER M4 ;
        RECT  23.676 13.584 23.76 13.608 ;
    END
  END i[38]
  PIN i[39]
    DIRECTION INPUT ;
    USE SIGNAL ;
    PORT
      LAYER M4 ;
        RECT  23.676 13.68 23.76 13.704 ;
    END
  END i[39]
  PIN i[3]
    DIRECTION INPUT ;
    USE SIGNAL ;
    PORT
      LAYER M4 ;
        RECT  23.676 10.224 23.76 10.248 ;
    END
  END i[3]
  PIN i[40]
    DIRECTION INPUT ;
    USE SIGNAL ;
    PORT
      LAYER M4 ;
        RECT  23.676 13.776 23.76 13.8 ;
    END
  END i[40]
  PIN i[41]
    DIRECTION INPUT ;
    USE SIGNAL ;
    PORT
      LAYER M4 ;
        RECT  23.676 13.872 23.76 13.896 ;
    END
  END i[41]
  PIN i[42]
    DIRECTION INPUT ;
    USE SIGNAL ;
    PORT
      LAYER M4 ;
        RECT  23.676 13.968 23.76 13.992 ;
    END
  END i[42]
  PIN i[43]
    DIRECTION INPUT ;
    USE SIGNAL ;
    PORT
      LAYER M4 ;
        RECT  23.676 14.064 23.76 14.088 ;
    END
  END i[43]
  PIN i[44]
    DIRECTION INPUT ;
    USE SIGNAL ;
    PORT
      LAYER M4 ;
        RECT  23.676 14.16 23.76 14.184 ;
    END
  END i[44]
  PIN i[45]
    DIRECTION INPUT ;
    USE SIGNAL ;
    PORT
      LAYER M4 ;
        RECT  23.676 14.256 23.76 14.28 ;
    END
  END i[45]
  PIN i[46]
    DIRECTION INPUT ;
    USE SIGNAL ;
    PORT
      LAYER M4 ;
        RECT  23.676 14.352 23.76 14.376 ;
    END
  END i[46]
  PIN i[47]
    DIRECTION INPUT ;
    USE SIGNAL ;
    PORT
      LAYER M4 ;
        RECT  23.676 14.448 23.76 14.472 ;
    END
  END i[47]
  PIN i[48]
    DIRECTION INPUT ;
    USE SIGNAL ;
    PORT
      LAYER M4 ;
        RECT  23.676 14.544 23.76 14.568 ;
    END
  END i[48]
  PIN i[49]
    DIRECTION INPUT ;
    USE SIGNAL ;
    PORT
      LAYER M4 ;
        RECT  23.676 14.64 23.76 14.664 ;
    END
  END i[49]
  PIN i[4]
    DIRECTION INPUT ;
    USE SIGNAL ;
    PORT
      LAYER M4 ;
        RECT  23.676 10.32 23.76 10.344 ;
    END
  END i[4]
  PIN i[50]
    DIRECTION INPUT ;
    USE SIGNAL ;
    PORT
      LAYER M4 ;
        RECT  23.676 14.736 23.76 14.76 ;
    END
  END i[50]
  PIN i[51]
    DIRECTION INPUT ;
    USE SIGNAL ;
    PORT
      LAYER M4 ;
        RECT  23.676 14.832 23.76 14.856 ;
    END
  END i[51]
  PIN i[52]
    DIRECTION INPUT ;
    USE SIGNAL ;
    PORT
      LAYER M4 ;
        RECT  23.676 14.928 23.76 14.952 ;
    END
  END i[52]
  PIN i[53]
    DIRECTION INPUT ;
    USE SIGNAL ;
    PORT
      LAYER M4 ;
        RECT  23.676 15.024 23.76 15.048 ;
    END
  END i[53]
  PIN i[54]
    DIRECTION INPUT ;
    USE SIGNAL ;
    PORT
      LAYER M4 ;
        RECT  23.676 15.12 23.76 15.144 ;
    END
  END i[54]
  PIN i[55]
    DIRECTION INPUT ;
    USE SIGNAL ;
    PORT
      LAYER M4 ;
        RECT  23.676 15.216 23.76 15.24 ;
    END
  END i[55]
  PIN i[56]
    DIRECTION INPUT ;
    USE SIGNAL ;
    PORT
      LAYER M4 ;
        RECT  23.676 15.312 23.76 15.336 ;
    END
  END i[56]
  PIN i[57]
    DIRECTION INPUT ;
    USE SIGNAL ;
    PORT
      LAYER M4 ;
        RECT  23.676 15.408 23.76 15.432 ;
    END
  END i[57]
  PIN i[58]
    DIRECTION INPUT ;
    USE SIGNAL ;
    PORT
      LAYER M4 ;
        RECT  23.676 15.504 23.76 15.528 ;
    END
  END i[58]
  PIN i[59]
    DIRECTION INPUT ;
    USE SIGNAL ;
    PORT
      LAYER M4 ;
        RECT  23.676 15.6 23.76 15.624 ;
    END
  END i[59]
  PIN i[5]
    DIRECTION INPUT ;
    USE SIGNAL ;
    PORT
      LAYER M4 ;
        RECT  23.676 10.416 23.76 10.44 ;
    END
  END i[5]
  PIN i[60]
    DIRECTION INPUT ;
    USE SIGNAL ;
    PORT
      LAYER M4 ;
        RECT  23.676 15.696 23.76 15.72 ;
    END
  END i[60]
  PIN i[61]
    DIRECTION INPUT ;
    USE SIGNAL ;
    PORT
      LAYER M4 ;
        RECT  23.676 15.792 23.76 15.816 ;
    END
  END i[61]
  PIN i[62]
    DIRECTION INPUT ;
    USE SIGNAL ;
    PORT
      LAYER M4 ;
        RECT  23.676 15.888 23.76 15.912 ;
    END
  END i[62]
  PIN i[63]
    DIRECTION INPUT ;
    USE SIGNAL ;
    PORT
      LAYER M4 ;
        RECT  23.676 15.984 23.76 16.008 ;
    END
  END i[63]
  PIN i[64]
    DIRECTION INPUT ;
    USE SIGNAL ;
    PORT
      LAYER M4 ;
        RECT  23.676 6.864 23.76 6.888 ;
    END
  END i[64]
  PIN i[65]
    DIRECTION INPUT ;
    USE SIGNAL ;
    PORT
      LAYER M4 ;
        RECT  23.676 6.96 23.76 6.984 ;
    END
  END i[65]
  PIN i[66]
    DIRECTION INPUT ;
    USE SIGNAL ;
    PORT
      LAYER M4 ;
        RECT  23.676 7.056 23.76 7.08 ;
    END
  END i[66]
  PIN i[67]
    DIRECTION INPUT ;
    USE SIGNAL ;
    PORT
      LAYER M4 ;
        RECT  23.676 7.152 23.76 7.176 ;
    END
  END i[67]
  PIN i[68]
    DIRECTION INPUT ;
    USE SIGNAL ;
    PORT
      LAYER M4 ;
        RECT  23.676 7.248 23.76 7.272 ;
    END
  END i[68]
  PIN i[69]
    DIRECTION INPUT ;
    USE SIGNAL ;
    PORT
      LAYER M4 ;
        RECT  23.676 7.344 23.76 7.368 ;
    END
  END i[69]
  PIN i[6]
    DIRECTION INPUT ;
    USE SIGNAL ;
    PORT
      LAYER M4 ;
        RECT  23.676 10.512 23.76 10.536 ;
    END
  END i[6]
  PIN i[70]
    DIRECTION INPUT ;
    USE SIGNAL ;
    PORT
      LAYER M4 ;
        RECT  23.676 7.44 23.76 7.464 ;
    END
  END i[70]
  PIN i[71]
    DIRECTION INPUT ;
    USE SIGNAL ;
    PORT
      LAYER M4 ;
        RECT  23.676 7.536 23.76 7.56 ;
    END
  END i[71]
  PIN i[72]
    DIRECTION INPUT ;
    USE SIGNAL ;
    PORT
      LAYER M4 ;
        RECT  23.676 7.632 23.76 7.656 ;
    END
  END i[72]
  PIN i[73]
    DIRECTION INPUT ;
    USE SIGNAL ;
    PORT
      LAYER M4 ;
        RECT  23.676 7.728 23.76 7.752 ;
    END
  END i[73]
  PIN i[74]
    DIRECTION INPUT ;
    USE SIGNAL ;
    PORT
      LAYER M4 ;
        RECT  23.676 7.824 23.76 7.848 ;
    END
  END i[74]
  PIN i[75]
    DIRECTION INPUT ;
    USE SIGNAL ;
    PORT
      LAYER M4 ;
        RECT  23.676 7.92 23.76 7.944 ;
    END
  END i[75]
  PIN i[76]
    DIRECTION INPUT ;
    USE SIGNAL ;
    PORT
      LAYER M4 ;
        RECT  23.676 8.016 23.76 8.04 ;
    END
  END i[76]
  PIN i[77]
    DIRECTION INPUT ;
    USE SIGNAL ;
    PORT
      LAYER M4 ;
        RECT  23.676 8.112 23.76 8.136 ;
    END
  END i[77]
  PIN i[78]
    DIRECTION INPUT ;
    USE SIGNAL ;
    PORT
      LAYER M4 ;
        RECT  23.676 8.208 23.76 8.232 ;
    END
  END i[78]
  PIN i[79]
    DIRECTION INPUT ;
    USE SIGNAL ;
    PORT
      LAYER M4 ;
        RECT  23.676 8.304 23.76 8.328 ;
    END
  END i[79]
  PIN i[7]
    DIRECTION INPUT ;
    USE SIGNAL ;
    PORT
      LAYER M4 ;
        RECT  23.676 10.608 23.76 10.632 ;
    END
  END i[7]
  PIN i[80]
    DIRECTION INPUT ;
    USE SIGNAL ;
    PORT
      LAYER M4 ;
        RECT  23.676 8.4 23.76 8.424 ;
    END
  END i[80]
  PIN i[81]
    DIRECTION INPUT ;
    USE SIGNAL ;
    PORT
      LAYER M4 ;
        RECT  23.676 8.496 23.76 8.52 ;
    END
  END i[81]
  PIN i[82]
    DIRECTION INPUT ;
    USE SIGNAL ;
    PORT
      LAYER M4 ;
        RECT  23.676 8.592 23.76 8.616 ;
    END
  END i[82]
  PIN i[83]
    DIRECTION INPUT ;
    USE SIGNAL ;
    PORT
      LAYER M4 ;
        RECT  23.676 8.688 23.76 8.712 ;
    END
  END i[83]
  PIN i[84]
    DIRECTION INPUT ;
    USE SIGNAL ;
    PORT
      LAYER M4 ;
        RECT  23.676 8.784 23.76 8.808 ;
    END
  END i[84]
  PIN i[85]
    DIRECTION INPUT ;
    USE SIGNAL ;
    PORT
      LAYER M4 ;
        RECT  23.676 8.88 23.76 8.904 ;
    END
  END i[85]
  PIN i[86]
    DIRECTION INPUT ;
    USE SIGNAL ;
    PORT
      LAYER M4 ;
        RECT  23.676 8.976 23.76 9 ;
    END
  END i[86]
  PIN i[87]
    DIRECTION INPUT ;
    USE SIGNAL ;
    PORT
      LAYER M4 ;
        RECT  23.676 9.072 23.76 9.096 ;
    END
  END i[87]
  PIN i[88]
    DIRECTION INPUT ;
    USE SIGNAL ;
    PORT
      LAYER M4 ;
        RECT  23.676 9.168 23.76 9.192 ;
    END
  END i[88]
  PIN i[89]
    DIRECTION INPUT ;
    USE SIGNAL ;
    PORT
      LAYER M4 ;
        RECT  23.676 9.264 23.76 9.288 ;
    END
  END i[89]
  PIN i[8]
    DIRECTION INPUT ;
    USE SIGNAL ;
    PORT
      LAYER M4 ;
        RECT  23.676 10.704 23.76 10.728 ;
    END
  END i[8]
  PIN i[90]
    DIRECTION INPUT ;
    USE SIGNAL ;
    PORT
      LAYER M4 ;
        RECT  23.676 9.36 23.76 9.384 ;
    END
  END i[90]
  PIN i[91]
    DIRECTION INPUT ;
    USE SIGNAL ;
    PORT
      LAYER M4 ;
        RECT  23.676 9.456 23.76 9.48 ;
    END
  END i[91]
  PIN i[92]
    DIRECTION INPUT ;
    USE SIGNAL ;
    PORT
      LAYER M4 ;
        RECT  23.676 9.552 23.76 9.576 ;
    END
  END i[92]
  PIN i[93]
    DIRECTION INPUT ;
    USE SIGNAL ;
    PORT
      LAYER M4 ;
        RECT  23.676 9.648 23.76 9.672 ;
    END
  END i[93]
  PIN i[94]
    DIRECTION INPUT ;
    USE SIGNAL ;
    PORT
      LAYER M4 ;
        RECT  23.676 9.744 23.76 9.768 ;
    END
  END i[94]
  PIN i[95]
    DIRECTION INPUT ;
    USE SIGNAL ;
    PORT
      LAYER M4 ;
        RECT  23.676 9.84 23.76 9.864 ;
    END
  END i[95]
  PIN i[96]
    DIRECTION INPUT ;
    USE SIGNAL ;
    PORT
      LAYER M4 ;
        RECT  23.676 3.792 23.76 3.816 ;
    END
  END i[96]
  PIN i[97]
    DIRECTION INPUT ;
    USE SIGNAL ;
    PORT
      LAYER M4 ;
        RECT  23.676 3.888 23.76 3.912 ;
    END
  END i[97]
  PIN i[98]
    DIRECTION INPUT ;
    USE SIGNAL ;
    PORT
      LAYER M4 ;
        RECT  23.676 3.984 23.76 4.008 ;
    END
  END i[98]
  PIN i[99]
    DIRECTION INPUT ;
    USE SIGNAL ;
    PORT
      LAYER M4 ;
        RECT  23.676 4.08 23.76 4.104 ;
    END
  END i[99]
  PIN i[9]
    DIRECTION INPUT ;
    USE SIGNAL ;
    PORT
      LAYER M4 ;
        RECT  23.676 10.8 23.76 10.824 ;
    END
  END i[9]
  PIN o[0]
    DIRECTION OUTPUT ;
    USE SIGNAL ;
    PORT
      LAYER M4 ;
        RECT  0 20.304 0.084 20.328 ;
    END
  END o[0]
  PIN o[100]
    DIRECTION OUTPUT ;
    USE SIGNAL ;
    PORT
      LAYER M4 ;
        RECT  0 4.56 0.084 4.584 ;
    END
  END o[100]
  PIN o[101]
    DIRECTION OUTPUT ;
    USE SIGNAL ;
    PORT
      LAYER M4 ;
        RECT  0 4.656 0.084 4.68 ;
    END
  END o[101]
  PIN o[102]
    DIRECTION OUTPUT ;
    USE SIGNAL ;
    PORT
      LAYER M4 ;
        RECT  0 4.752 0.084 4.776 ;
    END
  END o[102]
  PIN o[103]
    DIRECTION OUTPUT ;
    USE SIGNAL ;
    PORT
      LAYER M4 ;
        RECT  0 4.848 0.084 4.872 ;
    END
  END o[103]
  PIN o[104]
    DIRECTION OUTPUT ;
    USE SIGNAL ;
    PORT
      LAYER M4 ;
        RECT  0 4.944 0.084 4.968 ;
    END
  END o[104]
  PIN o[105]
    DIRECTION OUTPUT ;
    USE SIGNAL ;
    PORT
      LAYER M4 ;
        RECT  0 5.04 0.084 5.064 ;
    END
  END o[105]
  PIN o[106]
    DIRECTION OUTPUT ;
    USE SIGNAL ;
    PORT
      LAYER M4 ;
        RECT  0 5.136 0.084 5.16 ;
    END
  END o[106]
  PIN o[107]
    DIRECTION OUTPUT ;
    USE SIGNAL ;
    PORT
      LAYER M4 ;
        RECT  0 5.232 0.084 5.256 ;
    END
  END o[107]
  PIN o[108]
    DIRECTION OUTPUT ;
    USE SIGNAL ;
    PORT
      LAYER M4 ;
        RECT  0 5.328 0.084 5.352 ;
    END
  END o[108]
  PIN o[109]
    DIRECTION OUTPUT ;
    USE SIGNAL ;
    PORT
      LAYER M4 ;
        RECT  0 5.424 0.084 5.448 ;
    END
  END o[109]
  PIN o[10]
    DIRECTION OUTPUT ;
    USE SIGNAL ;
    PORT
      LAYER M4 ;
        RECT  0 21.264 0.084 21.288 ;
    END
  END o[10]
  PIN o[110]
    DIRECTION OUTPUT ;
    USE SIGNAL ;
    PORT
      LAYER M4 ;
        RECT  0 5.52 0.084 5.544 ;
    END
  END o[110]
  PIN o[111]
    DIRECTION OUTPUT ;
    USE SIGNAL ;
    PORT
      LAYER M4 ;
        RECT  0 5.616 0.084 5.64 ;
    END
  END o[111]
  PIN o[112]
    DIRECTION OUTPUT ;
    USE SIGNAL ;
    PORT
      LAYER M4 ;
        RECT  0 5.712 0.084 5.736 ;
    END
  END o[112]
  PIN o[113]
    DIRECTION OUTPUT ;
    USE SIGNAL ;
    PORT
      LAYER M4 ;
        RECT  0 5.808 0.084 5.832 ;
    END
  END o[113]
  PIN o[114]
    DIRECTION OUTPUT ;
    USE SIGNAL ;
    PORT
      LAYER M4 ;
        RECT  0 5.904 0.084 5.928 ;
    END
  END o[114]
  PIN o[115]
    DIRECTION OUTPUT ;
    USE SIGNAL ;
    PORT
      LAYER M4 ;
        RECT  0 6 0.084 6.024 ;
    END
  END o[115]
  PIN o[116]
    DIRECTION OUTPUT ;
    USE SIGNAL ;
    PORT
      LAYER M4 ;
        RECT  0 6.096 0.084 6.12 ;
    END
  END o[116]
  PIN o[117]
    DIRECTION OUTPUT ;
    USE SIGNAL ;
    PORT
      LAYER M4 ;
        RECT  0 6.192 0.084 6.216 ;
    END
  END o[117]
  PIN o[118]
    DIRECTION OUTPUT ;
    USE SIGNAL ;
    PORT
      LAYER M4 ;
        RECT  0 6.288 0.084 6.312 ;
    END
  END o[118]
  PIN o[119]
    DIRECTION OUTPUT ;
    USE SIGNAL ;
    PORT
      LAYER M4 ;
        RECT  0 6.384 0.084 6.408 ;
    END
  END o[119]
  PIN o[11]
    DIRECTION OUTPUT ;
    USE SIGNAL ;
    PORT
      LAYER M4 ;
        RECT  0 21.36 0.084 21.384 ;
    END
  END o[11]
  PIN o[120]
    DIRECTION OUTPUT ;
    USE SIGNAL ;
    PORT
      LAYER M4 ;
        RECT  0 6.48 0.084 6.504 ;
    END
  END o[120]
  PIN o[121]
    DIRECTION OUTPUT ;
    USE SIGNAL ;
    PORT
      LAYER M4 ;
        RECT  0 6.576 0.084 6.6 ;
    END
  END o[121]
  PIN o[122]
    DIRECTION OUTPUT ;
    USE SIGNAL ;
    PORT
      LAYER M4 ;
        RECT  0 6.672 0.084 6.696 ;
    END
  END o[122]
  PIN o[123]
    DIRECTION OUTPUT ;
    USE SIGNAL ;
    PORT
      LAYER M4 ;
        RECT  0 6.768 0.084 6.792 ;
    END
  END o[123]
  PIN o[124]
    DIRECTION OUTPUT ;
    USE SIGNAL ;
    PORT
      LAYER M4 ;
        RECT  0 6.864 0.084 6.888 ;
    END
  END o[124]
  PIN o[125]
    DIRECTION OUTPUT ;
    USE SIGNAL ;
    PORT
      LAYER M4 ;
        RECT  0 6.96 0.084 6.984 ;
    END
  END o[125]
  PIN o[126]
    DIRECTION OUTPUT ;
    USE SIGNAL ;
    PORT
      LAYER M4 ;
        RECT  0 7.056 0.084 7.08 ;
    END
  END o[126]
  PIN o[127]
    DIRECTION OUTPUT ;
    USE SIGNAL ;
    PORT
      LAYER M4 ;
        RECT  0 7.152 0.084 7.176 ;
    END
  END o[127]
  PIN o[128]
    DIRECTION OUTPUT ;
    USE SIGNAL ;
    PORT
      LAYER M4 ;
        RECT  0 17.232 0.084 17.256 ;
    END
  END o[128]
  PIN o[129]
    DIRECTION OUTPUT ;
    USE SIGNAL ;
    PORT
      LAYER M4 ;
        RECT  0 17.328 0.084 17.352 ;
    END
  END o[129]
  PIN o[12]
    DIRECTION OUTPUT ;
    USE SIGNAL ;
    PORT
      LAYER M4 ;
        RECT  0 21.456 0.084 21.48 ;
    END
  END o[12]
  PIN o[130]
    DIRECTION OUTPUT ;
    USE SIGNAL ;
    PORT
      LAYER M4 ;
        RECT  0 17.424 0.084 17.448 ;
    END
  END o[130]
  PIN o[131]
    DIRECTION OUTPUT ;
    USE SIGNAL ;
    PORT
      LAYER M4 ;
        RECT  0 17.52 0.084 17.544 ;
    END
  END o[131]
  PIN o[132]
    DIRECTION OUTPUT ;
    USE SIGNAL ;
    PORT
      LAYER M4 ;
        RECT  0 17.616 0.084 17.64 ;
    END
  END o[132]
  PIN o[133]
    DIRECTION OUTPUT ;
    USE SIGNAL ;
    PORT
      LAYER M4 ;
        RECT  0 17.712 0.084 17.736 ;
    END
  END o[133]
  PIN o[134]
    DIRECTION OUTPUT ;
    USE SIGNAL ;
    PORT
      LAYER M4 ;
        RECT  0 17.808 0.084 17.832 ;
    END
  END o[134]
  PIN o[135]
    DIRECTION OUTPUT ;
    USE SIGNAL ;
    PORT
      LAYER M4 ;
        RECT  0 17.904 0.084 17.928 ;
    END
  END o[135]
  PIN o[136]
    DIRECTION OUTPUT ;
    USE SIGNAL ;
    PORT
      LAYER M4 ;
        RECT  0 18 0.084 18.024 ;
    END
  END o[136]
  PIN o[137]
    DIRECTION OUTPUT ;
    USE SIGNAL ;
    PORT
      LAYER M4 ;
        RECT  0 18.096 0.084 18.12 ;
    END
  END o[137]
  PIN o[138]
    DIRECTION OUTPUT ;
    USE SIGNAL ;
    PORT
      LAYER M4 ;
        RECT  0 18.192 0.084 18.216 ;
    END
  END o[138]
  PIN o[139]
    DIRECTION OUTPUT ;
    USE SIGNAL ;
    PORT
      LAYER M4 ;
        RECT  0 18.288 0.084 18.312 ;
    END
  END o[139]
  PIN o[13]
    DIRECTION OUTPUT ;
    USE SIGNAL ;
    PORT
      LAYER M4 ;
        RECT  0 21.552 0.084 21.576 ;
    END
  END o[13]
  PIN o[140]
    DIRECTION OUTPUT ;
    USE SIGNAL ;
    PORT
      LAYER M4 ;
        RECT  0 18.384 0.084 18.408 ;
    END
  END o[140]
  PIN o[141]
    DIRECTION OUTPUT ;
    USE SIGNAL ;
    PORT
      LAYER M4 ;
        RECT  0 18.48 0.084 18.504 ;
    END
  END o[141]
  PIN o[142]
    DIRECTION OUTPUT ;
    USE SIGNAL ;
    PORT
      LAYER M4 ;
        RECT  0 18.576 0.084 18.6 ;
    END
  END o[142]
  PIN o[143]
    DIRECTION OUTPUT ;
    USE SIGNAL ;
    PORT
      LAYER M4 ;
        RECT  0 18.672 0.084 18.696 ;
    END
  END o[143]
  PIN o[144]
    DIRECTION OUTPUT ;
    USE SIGNAL ;
    PORT
      LAYER M4 ;
        RECT  0 18.768 0.084 18.792 ;
    END
  END o[144]
  PIN o[145]
    DIRECTION OUTPUT ;
    USE SIGNAL ;
    PORT
      LAYER M4 ;
        RECT  0 18.864 0.084 18.888 ;
    END
  END o[145]
  PIN o[146]
    DIRECTION OUTPUT ;
    USE SIGNAL ;
    PORT
      LAYER M4 ;
        RECT  0 18.96 0.084 18.984 ;
    END
  END o[146]
  PIN o[147]
    DIRECTION OUTPUT ;
    USE SIGNAL ;
    PORT
      LAYER M4 ;
        RECT  0 19.056 0.084 19.08 ;
    END
  END o[147]
  PIN o[148]
    DIRECTION OUTPUT ;
    USE SIGNAL ;
    PORT
      LAYER M4 ;
        RECT  0 19.152 0.084 19.176 ;
    END
  END o[148]
  PIN o[149]
    DIRECTION OUTPUT ;
    USE SIGNAL ;
    PORT
      LAYER M4 ;
        RECT  0 19.248 0.084 19.272 ;
    END
  END o[149]
  PIN o[14]
    DIRECTION OUTPUT ;
    USE SIGNAL ;
    PORT
      LAYER M4 ;
        RECT  0 21.648 0.084 21.672 ;
    END
  END o[14]
  PIN o[150]
    DIRECTION OUTPUT ;
    USE SIGNAL ;
    PORT
      LAYER M4 ;
        RECT  0 19.344 0.084 19.368 ;
    END
  END o[150]
  PIN o[151]
    DIRECTION OUTPUT ;
    USE SIGNAL ;
    PORT
      LAYER M4 ;
        RECT  0 19.44 0.084 19.464 ;
    END
  END o[151]
  PIN o[152]
    DIRECTION OUTPUT ;
    USE SIGNAL ;
    PORT
      LAYER M4 ;
        RECT  0 19.536 0.084 19.56 ;
    END
  END o[152]
  PIN o[153]
    DIRECTION OUTPUT ;
    USE SIGNAL ;
    PORT
      LAYER M4 ;
        RECT  0 19.632 0.084 19.656 ;
    END
  END o[153]
  PIN o[154]
    DIRECTION OUTPUT ;
    USE SIGNAL ;
    PORT
      LAYER M4 ;
        RECT  0 19.728 0.084 19.752 ;
    END
  END o[154]
  PIN o[155]
    DIRECTION OUTPUT ;
    USE SIGNAL ;
    PORT
      LAYER M4 ;
        RECT  0 19.824 0.084 19.848 ;
    END
  END o[155]
  PIN o[156]
    DIRECTION OUTPUT ;
    USE SIGNAL ;
    PORT
      LAYER M4 ;
        RECT  0 19.92 0.084 19.944 ;
    END
  END o[156]
  PIN o[157]
    DIRECTION OUTPUT ;
    USE SIGNAL ;
    PORT
      LAYER M4 ;
        RECT  0 20.016 0.084 20.04 ;
    END
  END o[157]
  PIN o[158]
    DIRECTION OUTPUT ;
    USE SIGNAL ;
    PORT
      LAYER M4 ;
        RECT  0 20.112 0.084 20.136 ;
    END
  END o[158]
  PIN o[159]
    DIRECTION OUTPUT ;
    USE SIGNAL ;
    PORT
      LAYER M4 ;
        RECT  0 20.208 0.084 20.232 ;
    END
  END o[159]
  PIN o[15]
    DIRECTION OUTPUT ;
    USE SIGNAL ;
    PORT
      LAYER M4 ;
        RECT  0 21.744 0.084 21.768 ;
    END
  END o[15]
  PIN o[160]
    DIRECTION OUTPUT ;
    USE SIGNAL ;
    PORT
      LAYER M4 ;
        RECT  0 14.16 0.084 14.184 ;
    END
  END o[160]
  PIN o[161]
    DIRECTION OUTPUT ;
    USE SIGNAL ;
    PORT
      LAYER M4 ;
        RECT  0 14.256 0.084 14.28 ;
    END
  END o[161]
  PIN o[162]
    DIRECTION OUTPUT ;
    USE SIGNAL ;
    PORT
      LAYER M4 ;
        RECT  0 14.352 0.084 14.376 ;
    END
  END o[162]
  PIN o[163]
    DIRECTION OUTPUT ;
    USE SIGNAL ;
    PORT
      LAYER M4 ;
        RECT  0 14.448 0.084 14.472 ;
    END
  END o[163]
  PIN o[164]
    DIRECTION OUTPUT ;
    USE SIGNAL ;
    PORT
      LAYER M4 ;
        RECT  0 14.544 0.084 14.568 ;
    END
  END o[164]
  PIN o[165]
    DIRECTION OUTPUT ;
    USE SIGNAL ;
    PORT
      LAYER M4 ;
        RECT  0 14.64 0.084 14.664 ;
    END
  END o[165]
  PIN o[166]
    DIRECTION OUTPUT ;
    USE SIGNAL ;
    PORT
      LAYER M4 ;
        RECT  0 14.736 0.084 14.76 ;
    END
  END o[166]
  PIN o[167]
    DIRECTION OUTPUT ;
    USE SIGNAL ;
    PORT
      LAYER M4 ;
        RECT  0 14.832 0.084 14.856 ;
    END
  END o[167]
  PIN o[168]
    DIRECTION OUTPUT ;
    USE SIGNAL ;
    PORT
      LAYER M4 ;
        RECT  0 14.928 0.084 14.952 ;
    END
  END o[168]
  PIN o[169]
    DIRECTION OUTPUT ;
    USE SIGNAL ;
    PORT
      LAYER M4 ;
        RECT  0 15.024 0.084 15.048 ;
    END
  END o[169]
  PIN o[16]
    DIRECTION OUTPUT ;
    USE SIGNAL ;
    PORT
      LAYER M4 ;
        RECT  0 21.84 0.084 21.864 ;
    END
  END o[16]
  PIN o[170]
    DIRECTION OUTPUT ;
    USE SIGNAL ;
    PORT
      LAYER M4 ;
        RECT  0 15.12 0.084 15.144 ;
    END
  END o[170]
  PIN o[171]
    DIRECTION OUTPUT ;
    USE SIGNAL ;
    PORT
      LAYER M4 ;
        RECT  0 15.216 0.084 15.24 ;
    END
  END o[171]
  PIN o[172]
    DIRECTION OUTPUT ;
    USE SIGNAL ;
    PORT
      LAYER M4 ;
        RECT  0 15.312 0.084 15.336 ;
    END
  END o[172]
  PIN o[173]
    DIRECTION OUTPUT ;
    USE SIGNAL ;
    PORT
      LAYER M4 ;
        RECT  0 15.408 0.084 15.432 ;
    END
  END o[173]
  PIN o[174]
    DIRECTION OUTPUT ;
    USE SIGNAL ;
    PORT
      LAYER M4 ;
        RECT  0 15.504 0.084 15.528 ;
    END
  END o[174]
  PIN o[175]
    DIRECTION OUTPUT ;
    USE SIGNAL ;
    PORT
      LAYER M4 ;
        RECT  0 15.6 0.084 15.624 ;
    END
  END o[175]
  PIN o[176]
    DIRECTION OUTPUT ;
    USE SIGNAL ;
    PORT
      LAYER M4 ;
        RECT  0 15.696 0.084 15.72 ;
    END
  END o[176]
  PIN o[177]
    DIRECTION OUTPUT ;
    USE SIGNAL ;
    PORT
      LAYER M4 ;
        RECT  0 15.792 0.084 15.816 ;
    END
  END o[177]
  PIN o[178]
    DIRECTION OUTPUT ;
    USE SIGNAL ;
    PORT
      LAYER M4 ;
        RECT  0 15.888 0.084 15.912 ;
    END
  END o[178]
  PIN o[179]
    DIRECTION OUTPUT ;
    USE SIGNAL ;
    PORT
      LAYER M4 ;
        RECT  0 15.984 0.084 16.008 ;
    END
  END o[179]
  PIN o[17]
    DIRECTION OUTPUT ;
    USE SIGNAL ;
    PORT
      LAYER M4 ;
        RECT  0 21.936 0.084 21.96 ;
    END
  END o[17]
  PIN o[180]
    DIRECTION OUTPUT ;
    USE SIGNAL ;
    PORT
      LAYER M4 ;
        RECT  0 16.08 0.084 16.104 ;
    END
  END o[180]
  PIN o[181]
    DIRECTION OUTPUT ;
    USE SIGNAL ;
    PORT
      LAYER M4 ;
        RECT  0 16.176 0.084 16.2 ;
    END
  END o[181]
  PIN o[182]
    DIRECTION OUTPUT ;
    USE SIGNAL ;
    PORT
      LAYER M4 ;
        RECT  0 16.272 0.084 16.296 ;
    END
  END o[182]
  PIN o[183]
    DIRECTION OUTPUT ;
    USE SIGNAL ;
    PORT
      LAYER M4 ;
        RECT  0 16.368 0.084 16.392 ;
    END
  END o[183]
  PIN o[184]
    DIRECTION OUTPUT ;
    USE SIGNAL ;
    PORT
      LAYER M4 ;
        RECT  0 16.464 0.084 16.488 ;
    END
  END o[184]
  PIN o[185]
    DIRECTION OUTPUT ;
    USE SIGNAL ;
    PORT
      LAYER M4 ;
        RECT  0 16.56 0.084 16.584 ;
    END
  END o[185]
  PIN o[186]
    DIRECTION OUTPUT ;
    USE SIGNAL ;
    PORT
      LAYER M4 ;
        RECT  0 16.656 0.084 16.68 ;
    END
  END o[186]
  PIN o[187]
    DIRECTION OUTPUT ;
    USE SIGNAL ;
    PORT
      LAYER M4 ;
        RECT  0 16.752 0.084 16.776 ;
    END
  END o[187]
  PIN o[188]
    DIRECTION OUTPUT ;
    USE SIGNAL ;
    PORT
      LAYER M4 ;
        RECT  0 16.848 0.084 16.872 ;
    END
  END o[188]
  PIN o[189]
    DIRECTION OUTPUT ;
    USE SIGNAL ;
    PORT
      LAYER M4 ;
        RECT  0 16.944 0.084 16.968 ;
    END
  END o[189]
  PIN o[18]
    DIRECTION OUTPUT ;
    USE SIGNAL ;
    PORT
      LAYER M4 ;
        RECT  0 22.032 0.084 22.056 ;
    END
  END o[18]
  PIN o[190]
    DIRECTION OUTPUT ;
    USE SIGNAL ;
    PORT
      LAYER M4 ;
        RECT  0 17.04 0.084 17.064 ;
    END
  END o[190]
  PIN o[191]
    DIRECTION OUTPUT ;
    USE SIGNAL ;
    PORT
      LAYER M4 ;
        RECT  0 17.136 0.084 17.16 ;
    END
  END o[191]
  PIN o[192]
    DIRECTION OUTPUT ;
    USE SIGNAL ;
    PORT
      LAYER M4 ;
        RECT  0 11.088 0.084 11.112 ;
    END
  END o[192]
  PIN o[193]
    DIRECTION OUTPUT ;
    USE SIGNAL ;
    PORT
      LAYER M4 ;
        RECT  0 11.184 0.084 11.208 ;
    END
  END o[193]
  PIN o[194]
    DIRECTION OUTPUT ;
    USE SIGNAL ;
    PORT
      LAYER M4 ;
        RECT  0 11.28 0.084 11.304 ;
    END
  END o[194]
  PIN o[195]
    DIRECTION OUTPUT ;
    USE SIGNAL ;
    PORT
      LAYER M4 ;
        RECT  0 11.376 0.084 11.4 ;
    END
  END o[195]
  PIN o[196]
    DIRECTION OUTPUT ;
    USE SIGNAL ;
    PORT
      LAYER M4 ;
        RECT  0 11.472 0.084 11.496 ;
    END
  END o[196]
  PIN o[197]
    DIRECTION OUTPUT ;
    USE SIGNAL ;
    PORT
      LAYER M4 ;
        RECT  0 11.568 0.084 11.592 ;
    END
  END o[197]
  PIN o[198]
    DIRECTION OUTPUT ;
    USE SIGNAL ;
    PORT
      LAYER M4 ;
        RECT  0 11.664 0.084 11.688 ;
    END
  END o[198]
  PIN o[199]
    DIRECTION OUTPUT ;
    USE SIGNAL ;
    PORT
      LAYER M4 ;
        RECT  0 11.76 0.084 11.784 ;
    END
  END o[199]
  PIN o[19]
    DIRECTION OUTPUT ;
    USE SIGNAL ;
    PORT
      LAYER M4 ;
        RECT  0 22.128 0.084 22.152 ;
    END
  END o[19]
  PIN o[1]
    DIRECTION OUTPUT ;
    USE SIGNAL ;
    PORT
      LAYER M4 ;
        RECT  0 20.4 0.084 20.424 ;
    END
  END o[1]
  PIN o[200]
    DIRECTION OUTPUT ;
    USE SIGNAL ;
    PORT
      LAYER M4 ;
        RECT  0 11.856 0.084 11.88 ;
    END
  END o[200]
  PIN o[201]
    DIRECTION OUTPUT ;
    USE SIGNAL ;
    PORT
      LAYER M4 ;
        RECT  0 11.952 0.084 11.976 ;
    END
  END o[201]
  PIN o[202]
    DIRECTION OUTPUT ;
    USE SIGNAL ;
    PORT
      LAYER M4 ;
        RECT  0 12.048 0.084 12.072 ;
    END
  END o[202]
  PIN o[203]
    DIRECTION OUTPUT ;
    USE SIGNAL ;
    PORT
      LAYER M4 ;
        RECT  0 12.144 0.084 12.168 ;
    END
  END o[203]
  PIN o[204]
    DIRECTION OUTPUT ;
    USE SIGNAL ;
    PORT
      LAYER M4 ;
        RECT  0 12.24 0.084 12.264 ;
    END
  END o[204]
  PIN o[205]
    DIRECTION OUTPUT ;
    USE SIGNAL ;
    PORT
      LAYER M4 ;
        RECT  0 12.336 0.084 12.36 ;
    END
  END o[205]
  PIN o[206]
    DIRECTION OUTPUT ;
    USE SIGNAL ;
    PORT
      LAYER M4 ;
        RECT  0 12.432 0.084 12.456 ;
    END
  END o[206]
  PIN o[207]
    DIRECTION OUTPUT ;
    USE SIGNAL ;
    PORT
      LAYER M4 ;
        RECT  0 12.528 0.084 12.552 ;
    END
  END o[207]
  PIN o[208]
    DIRECTION OUTPUT ;
    USE SIGNAL ;
    PORT
      LAYER M4 ;
        RECT  0 12.624 0.084 12.648 ;
    END
  END o[208]
  PIN o[209]
    DIRECTION OUTPUT ;
    USE SIGNAL ;
    PORT
      LAYER M4 ;
        RECT  0 12.72 0.084 12.744 ;
    END
  END o[209]
  PIN o[20]
    DIRECTION OUTPUT ;
    USE SIGNAL ;
    PORT
      LAYER M4 ;
        RECT  0 22.224 0.084 22.248 ;
    END
  END o[20]
  PIN o[210]
    DIRECTION OUTPUT ;
    USE SIGNAL ;
    PORT
      LAYER M4 ;
        RECT  0 12.816 0.084 12.84 ;
    END
  END o[210]
  PIN o[211]
    DIRECTION OUTPUT ;
    USE SIGNAL ;
    PORT
      LAYER M4 ;
        RECT  0 12.912 0.084 12.936 ;
    END
  END o[211]
  PIN o[212]
    DIRECTION OUTPUT ;
    USE SIGNAL ;
    PORT
      LAYER M4 ;
        RECT  0 13.008 0.084 13.032 ;
    END
  END o[212]
  PIN o[213]
    DIRECTION OUTPUT ;
    USE SIGNAL ;
    PORT
      LAYER M4 ;
        RECT  0 13.104 0.084 13.128 ;
    END
  END o[213]
  PIN o[214]
    DIRECTION OUTPUT ;
    USE SIGNAL ;
    PORT
      LAYER M4 ;
        RECT  0 13.2 0.084 13.224 ;
    END
  END o[214]
  PIN o[215]
    DIRECTION OUTPUT ;
    USE SIGNAL ;
    PORT
      LAYER M4 ;
        RECT  0 13.296 0.084 13.32 ;
    END
  END o[215]
  PIN o[216]
    DIRECTION OUTPUT ;
    USE SIGNAL ;
    PORT
      LAYER M4 ;
        RECT  0 13.392 0.084 13.416 ;
    END
  END o[216]
  PIN o[217]
    DIRECTION OUTPUT ;
    USE SIGNAL ;
    PORT
      LAYER M4 ;
        RECT  0 13.488 0.084 13.512 ;
    END
  END o[217]
  PIN o[218]
    DIRECTION OUTPUT ;
    USE SIGNAL ;
    PORT
      LAYER M4 ;
        RECT  0 13.584 0.084 13.608 ;
    END
  END o[218]
  PIN o[219]
    DIRECTION OUTPUT ;
    USE SIGNAL ;
    PORT
      LAYER M4 ;
        RECT  0 13.68 0.084 13.704 ;
    END
  END o[219]
  PIN o[21]
    DIRECTION OUTPUT ;
    USE SIGNAL ;
    PORT
      LAYER M4 ;
        RECT  0 22.32 0.084 22.344 ;
    END
  END o[21]
  PIN o[220]
    DIRECTION OUTPUT ;
    USE SIGNAL ;
    PORT
      LAYER M4 ;
        RECT  0 13.776 0.084 13.8 ;
    END
  END o[220]
  PIN o[221]
    DIRECTION OUTPUT ;
    USE SIGNAL ;
    PORT
      LAYER M4 ;
        RECT  0 13.872 0.084 13.896 ;
    END
  END o[221]
  PIN o[222]
    DIRECTION OUTPUT ;
    USE SIGNAL ;
    PORT
      LAYER M4 ;
        RECT  0 13.968 0.084 13.992 ;
    END
  END o[222]
  PIN o[223]
    DIRECTION OUTPUT ;
    USE SIGNAL ;
    PORT
      LAYER M4 ;
        RECT  0 14.064 0.084 14.088 ;
    END
  END o[223]
  PIN o[224]
    DIRECTION OUTPUT ;
    USE SIGNAL ;
    PORT
      LAYER M4 ;
        RECT  0 7.248 0.084 7.272 ;
    END
  END o[224]
  PIN o[225]
    DIRECTION OUTPUT ;
    USE SIGNAL ;
    PORT
      LAYER M4 ;
        RECT  0 7.344 0.084 7.368 ;
    END
  END o[225]
  PIN o[226]
    DIRECTION OUTPUT ;
    USE SIGNAL ;
    PORT
      LAYER M4 ;
        RECT  0 7.44 0.084 7.464 ;
    END
  END o[226]
  PIN o[227]
    DIRECTION OUTPUT ;
    USE SIGNAL ;
    PORT
      LAYER M4 ;
        RECT  0 7.536 0.084 7.56 ;
    END
  END o[227]
  PIN o[228]
    DIRECTION OUTPUT ;
    USE SIGNAL ;
    PORT
      LAYER M4 ;
        RECT  0 7.632 0.084 7.656 ;
    END
  END o[228]
  PIN o[229]
    DIRECTION OUTPUT ;
    USE SIGNAL ;
    PORT
      LAYER M4 ;
        RECT  0 7.728 0.084 7.752 ;
    END
  END o[229]
  PIN o[22]
    DIRECTION OUTPUT ;
    USE SIGNAL ;
    PORT
      LAYER M4 ;
        RECT  0 22.416 0.084 22.44 ;
    END
  END o[22]
  PIN o[230]
    DIRECTION OUTPUT ;
    USE SIGNAL ;
    PORT
      LAYER M4 ;
        RECT  0 7.824 0.084 7.848 ;
    END
  END o[230]
  PIN o[231]
    DIRECTION OUTPUT ;
    USE SIGNAL ;
    PORT
      LAYER M4 ;
        RECT  0 7.92 0.084 7.944 ;
    END
  END o[231]
  PIN o[232]
    DIRECTION OUTPUT ;
    USE SIGNAL ;
    PORT
      LAYER M4 ;
        RECT  0 8.016 0.084 8.04 ;
    END
  END o[232]
  PIN o[233]
    DIRECTION OUTPUT ;
    USE SIGNAL ;
    PORT
      LAYER M4 ;
        RECT  0 8.112 0.084 8.136 ;
    END
  END o[233]
  PIN o[234]
    DIRECTION OUTPUT ;
    USE SIGNAL ;
    PORT
      LAYER M4 ;
        RECT  0 8.208 0.084 8.232 ;
    END
  END o[234]
  PIN o[235]
    DIRECTION OUTPUT ;
    USE SIGNAL ;
    PORT
      LAYER M4 ;
        RECT  0 8.304 0.084 8.328 ;
    END
  END o[235]
  PIN o[236]
    DIRECTION OUTPUT ;
    USE SIGNAL ;
    PORT
      LAYER M4 ;
        RECT  0 8.4 0.084 8.424 ;
    END
  END o[236]
  PIN o[237]
    DIRECTION OUTPUT ;
    USE SIGNAL ;
    PORT
      LAYER M4 ;
        RECT  0 8.496 0.084 8.52 ;
    END
  END o[237]
  PIN o[238]
    DIRECTION OUTPUT ;
    USE SIGNAL ;
    PORT
      LAYER M4 ;
        RECT  0 8.592 0.084 8.616 ;
    END
  END o[238]
  PIN o[239]
    DIRECTION OUTPUT ;
    USE SIGNAL ;
    PORT
      LAYER M4 ;
        RECT  0 8.688 0.084 8.712 ;
    END
  END o[239]
  PIN o[23]
    DIRECTION OUTPUT ;
    USE SIGNAL ;
    PORT
      LAYER M4 ;
        RECT  0 22.512 0.084 22.536 ;
    END
  END o[23]
  PIN o[240]
    DIRECTION OUTPUT ;
    USE SIGNAL ;
    PORT
      LAYER M4 ;
        RECT  0 8.784 0.084 8.808 ;
    END
  END o[240]
  PIN o[241]
    DIRECTION OUTPUT ;
    USE SIGNAL ;
    PORT
      LAYER M4 ;
        RECT  0 8.88 0.084 8.904 ;
    END
  END o[241]
  PIN o[242]
    DIRECTION OUTPUT ;
    USE SIGNAL ;
    PORT
      LAYER M4 ;
        RECT  0 8.976 0.084 9 ;
    END
  END o[242]
  PIN o[243]
    DIRECTION OUTPUT ;
    USE SIGNAL ;
    PORT
      LAYER M4 ;
        RECT  0 9.072 0.084 9.096 ;
    END
  END o[243]
  PIN o[244]
    DIRECTION OUTPUT ;
    USE SIGNAL ;
    PORT
      LAYER M4 ;
        RECT  0 9.168 0.084 9.192 ;
    END
  END o[244]
  PIN o[245]
    DIRECTION OUTPUT ;
    USE SIGNAL ;
    PORT
      LAYER M4 ;
        RECT  0 9.264 0.084 9.288 ;
    END
  END o[245]
  PIN o[246]
    DIRECTION OUTPUT ;
    USE SIGNAL ;
    PORT
      LAYER M4 ;
        RECT  0 9.36 0.084 9.384 ;
    END
  END o[246]
  PIN o[247]
    DIRECTION OUTPUT ;
    USE SIGNAL ;
    PORT
      LAYER M4 ;
        RECT  0 9.456 0.084 9.48 ;
    END
  END o[247]
  PIN o[248]
    DIRECTION OUTPUT ;
    USE SIGNAL ;
    PORT
      LAYER M4 ;
        RECT  0 9.552 0.084 9.576 ;
    END
  END o[248]
  PIN o[249]
    DIRECTION OUTPUT ;
    USE SIGNAL ;
    PORT
      LAYER M4 ;
        RECT  0 9.648 0.084 9.672 ;
    END
  END o[249]
  PIN o[24]
    DIRECTION OUTPUT ;
    USE SIGNAL ;
    PORT
      LAYER M4 ;
        RECT  0 22.608 0.084 22.632 ;
    END
  END o[24]
  PIN o[250]
    DIRECTION OUTPUT ;
    USE SIGNAL ;
    PORT
      LAYER M4 ;
        RECT  0 9.744 0.084 9.768 ;
    END
  END o[250]
  PIN o[251]
    DIRECTION OUTPUT ;
    USE SIGNAL ;
    PORT
      LAYER M4 ;
        RECT  0 9.84 0.084 9.864 ;
    END
  END o[251]
  PIN o[252]
    DIRECTION OUTPUT ;
    USE SIGNAL ;
    PORT
      LAYER M4 ;
        RECT  0 9.936 0.084 9.96 ;
    END
  END o[252]
  PIN o[253]
    DIRECTION OUTPUT ;
    USE SIGNAL ;
    PORT
      LAYER M4 ;
        RECT  0 10.032 0.084 10.056 ;
    END
  END o[253]
  PIN o[254]
    DIRECTION OUTPUT ;
    USE SIGNAL ;
    PORT
      LAYER M4 ;
        RECT  0 10.128 0.084 10.152 ;
    END
  END o[254]
  PIN o[255]
    DIRECTION OUTPUT ;
    USE SIGNAL ;
    PORT
      LAYER M4 ;
        RECT  0 10.224 0.084 10.248 ;
    END
  END o[255]
  PIN o[256]
    DIRECTION OUTPUT ;
    USE SIGNAL ;
    PORT
      LAYER M4 ;
        RECT  0 2.256 0.084 2.28 ;
    END
  END o[256]
  PIN o[257]
    DIRECTION OUTPUT ;
    USE SIGNAL ;
    PORT
      LAYER M4 ;
        RECT  0 2.352 0.084 2.376 ;
    END
  END o[257]
  PIN o[258]
    DIRECTION OUTPUT ;
    USE SIGNAL ;
    PORT
      LAYER M4 ;
        RECT  0 2.448 0.084 2.472 ;
    END
  END o[258]
  PIN o[259]
    DIRECTION OUTPUT ;
    USE SIGNAL ;
    PORT
      LAYER M4 ;
        RECT  0 2.544 0.084 2.568 ;
    END
  END o[259]
  PIN o[25]
    DIRECTION OUTPUT ;
    USE SIGNAL ;
    PORT
      LAYER M4 ;
        RECT  0 22.704 0.084 22.728 ;
    END
  END o[25]
  PIN o[260]
    DIRECTION OUTPUT ;
    USE SIGNAL ;
    PORT
      LAYER M4 ;
        RECT  0 2.64 0.084 2.664 ;
    END
  END o[260]
  PIN o[261]
    DIRECTION OUTPUT ;
    USE SIGNAL ;
    PORT
      LAYER M4 ;
        RECT  0 2.736 0.084 2.76 ;
    END
  END o[261]
  PIN o[262]
    DIRECTION OUTPUT ;
    USE SIGNAL ;
    PORT
      LAYER M4 ;
        RECT  0 2.832 0.084 2.856 ;
    END
  END o[262]
  PIN o[263]
    DIRECTION OUTPUT ;
    USE SIGNAL ;
    PORT
      LAYER M4 ;
        RECT  0 2.928 0.084 2.952 ;
    END
  END o[263]
  PIN o[264]
    DIRECTION OUTPUT ;
    USE SIGNAL ;
    PORT
      LAYER M4 ;
        RECT  0 3.024 0.084 3.048 ;
    END
  END o[264]
  PIN o[265]
    DIRECTION OUTPUT ;
    USE SIGNAL ;
    PORT
      LAYER M4 ;
        RECT  0 3.12 0.084 3.144 ;
    END
  END o[265]
  PIN o[266]
    DIRECTION OUTPUT ;
    USE SIGNAL ;
    PORT
      LAYER M4 ;
        RECT  0 3.216 0.084 3.24 ;
    END
  END o[266]
  PIN o[267]
    DIRECTION OUTPUT ;
    USE SIGNAL ;
    PORT
      LAYER M4 ;
        RECT  0 3.312 0.084 3.336 ;
    END
  END o[267]
  PIN o[268]
    DIRECTION OUTPUT ;
    USE SIGNAL ;
    PORT
      LAYER M4 ;
        RECT  0 3.408 0.084 3.432 ;
    END
  END o[268]
  PIN o[269]
    DIRECTION OUTPUT ;
    USE SIGNAL ;
    PORT
      LAYER M4 ;
        RECT  0 3.504 0.084 3.528 ;
    END
  END o[269]
  PIN o[26]
    DIRECTION OUTPUT ;
    USE SIGNAL ;
    PORT
      LAYER M4 ;
        RECT  0 22.8 0.084 22.824 ;
    END
  END o[26]
  PIN o[270]
    DIRECTION OUTPUT ;
    USE SIGNAL ;
    PORT
      LAYER M4 ;
        RECT  0 3.6 0.084 3.624 ;
    END
  END o[270]
  PIN o[271]
    DIRECTION OUTPUT ;
    USE SIGNAL ;
    PORT
      LAYER M4 ;
        RECT  0 3.696 0.084 3.72 ;
    END
  END o[271]
  PIN o[272]
    DIRECTION OUTPUT ;
    USE SIGNAL ;
    PORT
      LAYER M4 ;
        RECT  0 3.792 0.084 3.816 ;
    END
  END o[272]
  PIN o[273]
    DIRECTION OUTPUT ;
    USE SIGNAL ;
    PORT
      LAYER M4 ;
        RECT  0 3.888 0.084 3.912 ;
    END
  END o[273]
  PIN o[274]
    DIRECTION OUTPUT ;
    USE SIGNAL ;
    PORT
      LAYER M4 ;
        RECT  0 3.984 0.084 4.008 ;
    END
  END o[274]
  PIN o[275]
    DIRECTION OUTPUT ;
    USE SIGNAL ;
    PORT
      LAYER M4 ;
        RECT  0 4.08 0.084 4.104 ;
    END
  END o[275]
  PIN o[27]
    DIRECTION OUTPUT ;
    USE SIGNAL ;
    PORT
      LAYER M4 ;
        RECT  0 22.896 0.084 22.92 ;
    END
  END o[27]
  PIN o[28]
    DIRECTION OUTPUT ;
    USE SIGNAL ;
    PORT
      LAYER M4 ;
        RECT  0 22.992 0.084 23.016 ;
    END
  END o[28]
  PIN o[29]
    DIRECTION OUTPUT ;
    USE SIGNAL ;
    PORT
      LAYER M4 ;
        RECT  0 23.088 0.084 23.112 ;
    END
  END o[29]
  PIN o[2]
    DIRECTION OUTPUT ;
    USE SIGNAL ;
    PORT
      LAYER M4 ;
        RECT  0 20.496 0.084 20.52 ;
    END
  END o[2]
  PIN o[30]
    DIRECTION OUTPUT ;
    USE SIGNAL ;
    PORT
      LAYER M4 ;
        RECT  0 23.184 0.084 23.208 ;
    END
  END o[30]
  PIN o[31]
    DIRECTION OUTPUT ;
    USE SIGNAL ;
    PORT
      LAYER M4 ;
        RECT  0 23.28 0.084 23.304 ;
    END
  END o[31]
  PIN o[32]
    DIRECTION OUTPUT ;
    USE SIGNAL ;
    PORT
      LAYER M4 ;
        RECT  0 26.448 0.084 26.472 ;
    END
  END o[32]
  PIN o[33]
    DIRECTION OUTPUT ;
    USE SIGNAL ;
    PORT
      LAYER M4 ;
        RECT  0 26.544 0.084 26.568 ;
    END
  END o[33]
  PIN o[34]
    DIRECTION OUTPUT ;
    USE SIGNAL ;
    PORT
      LAYER M4 ;
        RECT  0 26.64 0.084 26.664 ;
    END
  END o[34]
  PIN o[35]
    DIRECTION OUTPUT ;
    USE SIGNAL ;
    PORT
      LAYER M4 ;
        RECT  0 26.736 0.084 26.76 ;
    END
  END o[35]
  PIN o[36]
    DIRECTION OUTPUT ;
    USE SIGNAL ;
    PORT
      LAYER M4 ;
        RECT  0 26.832 0.084 26.856 ;
    END
  END o[36]
  PIN o[37]
    DIRECTION OUTPUT ;
    USE SIGNAL ;
    PORT
      LAYER M4 ;
        RECT  0 26.928 0.084 26.952 ;
    END
  END o[37]
  PIN o[38]
    DIRECTION OUTPUT ;
    USE SIGNAL ;
    PORT
      LAYER M4 ;
        RECT  0 27.024 0.084 27.048 ;
    END
  END o[38]
  PIN o[39]
    DIRECTION OUTPUT ;
    USE SIGNAL ;
    PORT
      LAYER M4 ;
        RECT  0 27.12 0.084 27.144 ;
    END
  END o[39]
  PIN o[3]
    DIRECTION OUTPUT ;
    USE SIGNAL ;
    PORT
      LAYER M4 ;
        RECT  0 20.592 0.084 20.616 ;
    END
  END o[3]
  PIN o[40]
    DIRECTION OUTPUT ;
    USE SIGNAL ;
    PORT
      LAYER M4 ;
        RECT  0 27.216 0.084 27.24 ;
    END
  END o[40]
  PIN o[41]
    DIRECTION OUTPUT ;
    USE SIGNAL ;
    PORT
      LAYER M4 ;
        RECT  0 27.312 0.084 27.336 ;
    END
  END o[41]
  PIN o[42]
    DIRECTION OUTPUT ;
    USE SIGNAL ;
    PORT
      LAYER M4 ;
        RECT  0 27.408 0.084 27.432 ;
    END
  END o[42]
  PIN o[43]
    DIRECTION OUTPUT ;
    USE SIGNAL ;
    PORT
      LAYER M4 ;
        RECT  0 27.504 0.084 27.528 ;
    END
  END o[43]
  PIN o[44]
    DIRECTION OUTPUT ;
    USE SIGNAL ;
    PORT
      LAYER M4 ;
        RECT  0 27.6 0.084 27.624 ;
    END
  END o[44]
  PIN o[45]
    DIRECTION OUTPUT ;
    USE SIGNAL ;
    PORT
      LAYER M4 ;
        RECT  0 27.696 0.084 27.72 ;
    END
  END o[45]
  PIN o[46]
    DIRECTION OUTPUT ;
    USE SIGNAL ;
    PORT
      LAYER M4 ;
        RECT  0 27.792 0.084 27.816 ;
    END
  END o[46]
  PIN o[47]
    DIRECTION OUTPUT ;
    USE SIGNAL ;
    PORT
      LAYER M4 ;
        RECT  0 27.888 0.084 27.912 ;
    END
  END o[47]
  PIN o[48]
    DIRECTION OUTPUT ;
    USE SIGNAL ;
    PORT
      LAYER M4 ;
        RECT  0 27.984 0.084 28.008 ;
    END
  END o[48]
  PIN o[49]
    DIRECTION OUTPUT ;
    USE SIGNAL ;
    PORT
      LAYER M4 ;
        RECT  0 28.08 0.084 28.104 ;
    END
  END o[49]
  PIN o[4]
    DIRECTION OUTPUT ;
    USE SIGNAL ;
    PORT
      LAYER M4 ;
        RECT  0 20.688 0.084 20.712 ;
    END
  END o[4]
  PIN o[50]
    DIRECTION OUTPUT ;
    USE SIGNAL ;
    PORT
      LAYER M4 ;
        RECT  0 28.176 0.084 28.2 ;
    END
  END o[50]
  PIN o[51]
    DIRECTION OUTPUT ;
    USE SIGNAL ;
    PORT
      LAYER M4 ;
        RECT  0 28.272 0.084 28.296 ;
    END
  END o[51]
  PIN o[52]
    DIRECTION OUTPUT ;
    USE SIGNAL ;
    PORT
      LAYER M4 ;
        RECT  0 28.368 0.084 28.392 ;
    END
  END o[52]
  PIN o[53]
    DIRECTION OUTPUT ;
    USE SIGNAL ;
    PORT
      LAYER M4 ;
        RECT  0 28.464 0.084 28.488 ;
    END
  END o[53]
  PIN o[54]
    DIRECTION OUTPUT ;
    USE SIGNAL ;
    PORT
      LAYER M4 ;
        RECT  0 28.56 0.084 28.584 ;
    END
  END o[54]
  PIN o[55]
    DIRECTION OUTPUT ;
    USE SIGNAL ;
    PORT
      LAYER M4 ;
        RECT  0 28.656 0.084 28.68 ;
    END
  END o[55]
  PIN o[56]
    DIRECTION OUTPUT ;
    USE SIGNAL ;
    PORT
      LAYER M4 ;
        RECT  0 28.752 0.084 28.776 ;
    END
  END o[56]
  PIN o[57]
    DIRECTION OUTPUT ;
    USE SIGNAL ;
    PORT
      LAYER M4 ;
        RECT  0 28.848 0.084 28.872 ;
    END
  END o[57]
  PIN o[58]
    DIRECTION OUTPUT ;
    USE SIGNAL ;
    PORT
      LAYER M4 ;
        RECT  0 28.944 0.084 28.968 ;
    END
  END o[58]
  PIN o[59]
    DIRECTION OUTPUT ;
    USE SIGNAL ;
    PORT
      LAYER M4 ;
        RECT  0 29.04 0.084 29.064 ;
    END
  END o[59]
  PIN o[5]
    DIRECTION OUTPUT ;
    USE SIGNAL ;
    PORT
      LAYER M4 ;
        RECT  0 20.784 0.084 20.808 ;
    END
  END o[5]
  PIN o[60]
    DIRECTION OUTPUT ;
    USE SIGNAL ;
    PORT
      LAYER M4 ;
        RECT  0 29.136 0.084 29.16 ;
    END
  END o[60]
  PIN o[61]
    DIRECTION OUTPUT ;
    USE SIGNAL ;
    PORT
      LAYER M4 ;
        RECT  0 29.232 0.084 29.256 ;
    END
  END o[61]
  PIN o[62]
    DIRECTION OUTPUT ;
    USE SIGNAL ;
    PORT
      LAYER M4 ;
        RECT  0 29.328 0.084 29.352 ;
    END
  END o[62]
  PIN o[63]
    DIRECTION OUTPUT ;
    USE SIGNAL ;
    PORT
      LAYER M4 ;
        RECT  0 29.424 0.084 29.448 ;
    END
  END o[63]
  PIN o[64]
    DIRECTION OUTPUT ;
    USE SIGNAL ;
    PORT
      LAYER M4 ;
        RECT  0 23.376 0.084 23.4 ;
    END
  END o[64]
  PIN o[65]
    DIRECTION OUTPUT ;
    USE SIGNAL ;
    PORT
      LAYER M4 ;
        RECT  0 23.472 0.084 23.496 ;
    END
  END o[65]
  PIN o[66]
    DIRECTION OUTPUT ;
    USE SIGNAL ;
    PORT
      LAYER M4 ;
        RECT  0 23.568 0.084 23.592 ;
    END
  END o[66]
  PIN o[67]
    DIRECTION OUTPUT ;
    USE SIGNAL ;
    PORT
      LAYER M4 ;
        RECT  0 23.664 0.084 23.688 ;
    END
  END o[67]
  PIN o[68]
    DIRECTION OUTPUT ;
    USE SIGNAL ;
    PORT
      LAYER M4 ;
        RECT  0 23.76 0.084 23.784 ;
    END
  END o[68]
  PIN o[69]
    DIRECTION OUTPUT ;
    USE SIGNAL ;
    PORT
      LAYER M4 ;
        RECT  0 23.856 0.084 23.88 ;
    END
  END o[69]
  PIN o[6]
    DIRECTION OUTPUT ;
    USE SIGNAL ;
    PORT
      LAYER M4 ;
        RECT  0 20.88 0.084 20.904 ;
    END
  END o[6]
  PIN o[70]
    DIRECTION OUTPUT ;
    USE SIGNAL ;
    PORT
      LAYER M4 ;
        RECT  0 23.952 0.084 23.976 ;
    END
  END o[70]
  PIN o[71]
    DIRECTION OUTPUT ;
    USE SIGNAL ;
    PORT
      LAYER M4 ;
        RECT  0 24.048 0.084 24.072 ;
    END
  END o[71]
  PIN o[72]
    DIRECTION OUTPUT ;
    USE SIGNAL ;
    PORT
      LAYER M4 ;
        RECT  0 24.144 0.084 24.168 ;
    END
  END o[72]
  PIN o[73]
    DIRECTION OUTPUT ;
    USE SIGNAL ;
    PORT
      LAYER M4 ;
        RECT  0 24.24 0.084 24.264 ;
    END
  END o[73]
  PIN o[74]
    DIRECTION OUTPUT ;
    USE SIGNAL ;
    PORT
      LAYER M4 ;
        RECT  0 24.336 0.084 24.36 ;
    END
  END o[74]
  PIN o[75]
    DIRECTION OUTPUT ;
    USE SIGNAL ;
    PORT
      LAYER M4 ;
        RECT  0 24.432 0.084 24.456 ;
    END
  END o[75]
  PIN o[76]
    DIRECTION OUTPUT ;
    USE SIGNAL ;
    PORT
      LAYER M4 ;
        RECT  0 24.528 0.084 24.552 ;
    END
  END o[76]
  PIN o[77]
    DIRECTION OUTPUT ;
    USE SIGNAL ;
    PORT
      LAYER M4 ;
        RECT  0 24.624 0.084 24.648 ;
    END
  END o[77]
  PIN o[78]
    DIRECTION OUTPUT ;
    USE SIGNAL ;
    PORT
      LAYER M4 ;
        RECT  0 24.72 0.084 24.744 ;
    END
  END o[78]
  PIN o[79]
    DIRECTION OUTPUT ;
    USE SIGNAL ;
    PORT
      LAYER M4 ;
        RECT  0 24.816 0.084 24.84 ;
    END
  END o[79]
  PIN o[7]
    DIRECTION OUTPUT ;
    USE SIGNAL ;
    PORT
      LAYER M4 ;
        RECT  0 20.976 0.084 21 ;
    END
  END o[7]
  PIN o[80]
    DIRECTION OUTPUT ;
    USE SIGNAL ;
    PORT
      LAYER M4 ;
        RECT  0 24.912 0.084 24.936 ;
    END
  END o[80]
  PIN o[81]
    DIRECTION OUTPUT ;
    USE SIGNAL ;
    PORT
      LAYER M4 ;
        RECT  0 25.008 0.084 25.032 ;
    END
  END o[81]
  PIN o[82]
    DIRECTION OUTPUT ;
    USE SIGNAL ;
    PORT
      LAYER M4 ;
        RECT  0 25.104 0.084 25.128 ;
    END
  END o[82]
  PIN o[83]
    DIRECTION OUTPUT ;
    USE SIGNAL ;
    PORT
      LAYER M4 ;
        RECT  0 25.2 0.084 25.224 ;
    END
  END o[83]
  PIN o[84]
    DIRECTION OUTPUT ;
    USE SIGNAL ;
    PORT
      LAYER M4 ;
        RECT  0 25.296 0.084 25.32 ;
    END
  END o[84]
  PIN o[85]
    DIRECTION OUTPUT ;
    USE SIGNAL ;
    PORT
      LAYER M4 ;
        RECT  0 25.392 0.084 25.416 ;
    END
  END o[85]
  PIN o[86]
    DIRECTION OUTPUT ;
    USE SIGNAL ;
    PORT
      LAYER M4 ;
        RECT  0 25.488 0.084 25.512 ;
    END
  END o[86]
  PIN o[87]
    DIRECTION OUTPUT ;
    USE SIGNAL ;
    PORT
      LAYER M4 ;
        RECT  0 25.584 0.084 25.608 ;
    END
  END o[87]
  PIN o[88]
    DIRECTION OUTPUT ;
    USE SIGNAL ;
    PORT
      LAYER M4 ;
        RECT  0 25.68 0.084 25.704 ;
    END
  END o[88]
  PIN o[89]
    DIRECTION OUTPUT ;
    USE SIGNAL ;
    PORT
      LAYER M4 ;
        RECT  0 25.776 0.084 25.8 ;
    END
  END o[89]
  PIN o[8]
    DIRECTION OUTPUT ;
    USE SIGNAL ;
    PORT
      LAYER M4 ;
        RECT  0 21.072 0.084 21.096 ;
    END
  END o[8]
  PIN o[90]
    DIRECTION OUTPUT ;
    USE SIGNAL ;
    PORT
      LAYER M4 ;
        RECT  0 25.872 0.084 25.896 ;
    END
  END o[90]
  PIN o[91]
    DIRECTION OUTPUT ;
    USE SIGNAL ;
    PORT
      LAYER M4 ;
        RECT  0 25.968 0.084 25.992 ;
    END
  END o[91]
  PIN o[92]
    DIRECTION OUTPUT ;
    USE SIGNAL ;
    PORT
      LAYER M4 ;
        RECT  0 26.064 0.084 26.088 ;
    END
  END o[92]
  PIN o[93]
    DIRECTION OUTPUT ;
    USE SIGNAL ;
    PORT
      LAYER M4 ;
        RECT  0 26.16 0.084 26.184 ;
    END
  END o[93]
  PIN o[94]
    DIRECTION OUTPUT ;
    USE SIGNAL ;
    PORT
      LAYER M4 ;
        RECT  0 26.256 0.084 26.28 ;
    END
  END o[94]
  PIN o[95]
    DIRECTION OUTPUT ;
    USE SIGNAL ;
    PORT
      LAYER M4 ;
        RECT  0 26.352 0.084 26.376 ;
    END
  END o[95]
  PIN o[96]
    DIRECTION OUTPUT ;
    USE SIGNAL ;
    PORT
      LAYER M4 ;
        RECT  0 4.176 0.084 4.2 ;
    END
  END o[96]
  PIN o[97]
    DIRECTION OUTPUT ;
    USE SIGNAL ;
    PORT
      LAYER M4 ;
        RECT  0 4.272 0.084 4.296 ;
    END
  END o[97]
  PIN o[98]
    DIRECTION OUTPUT ;
    USE SIGNAL ;
    PORT
      LAYER M4 ;
        RECT  0 4.368 0.084 4.392 ;
    END
  END o[98]
  PIN o[99]
    DIRECTION OUTPUT ;
    USE SIGNAL ;
    PORT
      LAYER M4 ;
        RECT  0 4.464 0.084 4.488 ;
    END
  END o[99]
  PIN o[9]
    DIRECTION OUTPUT ;
    USE SIGNAL ;
    PORT
      LAYER M4 ;
        RECT  0 21.168 0.084 21.192 ;
    END
  END o[9]
  PIN rs
    DIRECTION INPUT ;
    USE SIGNAL ;
    PORT
      LAYER M5 ;
        RECT  17.04 30.156 17.064 30.24 ;
    END
  END rs
  PIN VDD
    DIRECTION INOUT ;
    USE POWER ;
    PORT
      LAYER M5 ;
        RECT  18.792 2.151 18.912 28.089 ;
        RECT  13.392 2.151 13.512 28.089 ;
        RECT  7.992 2.151 8.112 28.089 ;
        RECT  2.592 2.151 2.712 28.089 ;
    END
  END VDD
  PIN VSS
    DIRECTION INOUT ;
    USE GROUND ;
    PORT
      LAYER M5 ;
        RECT  18.6 2.137 18.72 28.103 ;
        RECT  13.2 2.137 13.32 28.103 ;
        RECT  7.8 2.137 7.92 28.103 ;
        RECT  2.4 2.137 2.52 28.103 ;
    END
  END VSS
  # OT_OBS_CLOSED layer=M5 d_um=1.536 added=61
  OBS
    LAYER RVTN ;
     RECT  2.16 2.16 21.6 2.295 ;
     RECT  2.16 2.565 21.6 2.835 ;
     RECT  2.16 3.105 21.6 3.375 ;
     RECT  2.16 3.645 21.6 3.915 ;
     RECT  2.16 4.185 21.6 4.455 ;
     RECT  2.16 4.725 21.6 4.995 ;
     RECT  2.16 5.265 21.6 5.535 ;
     RECT  2.16 5.805 21.6 6.075 ;
     RECT  2.16 6.345 21.6 6.615 ;
     RECT  2.16 6.885 21.6 7.155 ;
     RECT  2.16 7.425 21.6 7.695 ;
     RECT  2.16 7.965 21.6 8.235 ;
     RECT  2.16 8.505 21.6 8.775 ;
     RECT  2.16 9.045 21.6 9.315 ;
     RECT  2.16 9.585 21.6 9.855 ;
     RECT  2.16 10.125 21.6 10.395 ;
     RECT  2.16 10.665 21.6 10.935 ;
     RECT  2.16 11.205 21.6 11.475 ;
     RECT  2.16 11.745 21.6 12.015 ;
     RECT  2.16 12.285 21.6 12.555 ;
     RECT  2.16 12.825 21.6 13.095 ;
     RECT  2.16 13.365 21.6 13.635 ;
     RECT  2.16 13.905 21.6 14.175 ;
     RECT  2.16 14.445 21.6 14.715 ;
     RECT  2.16 14.985 21.6 15.255 ;
     RECT  2.16 15.525 21.6 15.795 ;
     RECT  2.16 16.065 21.6 16.335 ;
     RECT  2.16 16.605 21.6 16.875 ;
     RECT  2.16 17.145 21.6 17.415 ;
     RECT  2.16 17.685 21.6 17.955 ;
     RECT  2.16 18.225 21.6 18.495 ;
     RECT  2.16 18.765 21.6 19.035 ;
     RECT  2.16 19.305 21.6 19.575 ;
     RECT  2.16 19.845 21.6 20.115 ;
     RECT  2.16 20.385 21.6 20.655 ;
     RECT  2.16 20.925 21.6 21.195 ;
     RECT  2.16 21.465 21.6 21.735 ;
     RECT  2.16 22.005 21.6 22.275 ;
     RECT  2.16 22.545 21.6 22.815 ;
     RECT  2.16 23.085 21.6 23.355 ;
     RECT  2.16 23.625 21.6 23.895 ;
     RECT  2.16 24.165 21.6 24.435 ;
     RECT  2.16 24.705 21.6 24.975 ;
     RECT  2.16 25.245 21.6 25.515 ;
     RECT  2.16 25.785 21.6 26.055 ;
     RECT  2.16 26.325 21.6 26.595 ;
     RECT  2.16 26.865 21.6 27.135 ;
     RECT  2.16 27.405 21.6 27.675 ;
     RECT  2.16 27.945 21.6 28.08 ;
    LAYER RVTP ;
     RECT  2.16 2.295 21.6 2.565 ;
     RECT  2.16 2.835 21.6 3.105 ;
     RECT  2.16 3.375 21.6 3.645 ;
     RECT  2.16 3.915 21.6 4.185 ;
     RECT  2.16 4.455 21.6 4.725 ;
     RECT  2.16 4.995 21.6 5.265 ;
     RECT  2.16 5.535 21.6 5.805 ;
     RECT  2.16 6.075 21.6 6.345 ;
     RECT  2.16 6.615 21.6 6.885 ;
     RECT  2.16 7.155 21.6 7.425 ;
     RECT  2.16 7.695 21.6 7.965 ;
     RECT  2.16 8.235 21.6 8.505 ;
     RECT  2.16 8.775 21.6 9.045 ;
     RECT  2.16 9.315 21.6 9.585 ;
     RECT  2.16 9.855 21.6 10.125 ;
     RECT  2.16 10.395 21.6 10.665 ;
     RECT  2.16 10.935 21.6 11.205 ;
     RECT  2.16 11.475 21.6 11.745 ;
     RECT  2.16 12.015 21.6 12.285 ;
     RECT  2.16 12.555 21.6 12.825 ;
     RECT  2.16 13.095 21.6 13.365 ;
     RECT  2.16 13.635 21.6 13.905 ;
     RECT  2.16 14.175 21.6 14.445 ;
     RECT  2.16 14.715 21.6 14.985 ;
     RECT  2.16 15.255 21.6 15.525 ;
     RECT  2.16 15.795 21.6 16.065 ;
     RECT  2.16 16.335 21.6 16.605 ;
     RECT  2.16 16.875 21.6 17.145 ;
     RECT  2.16 17.415 21.6 17.685 ;
     RECT  2.16 17.955 21.6 18.225 ;
     RECT  2.16 18.495 21.6 18.765 ;
     RECT  2.16 19.035 21.6 19.305 ;
     RECT  2.16 19.575 21.6 19.845 ;
     RECT  2.16 20.115 21.6 20.385 ;
     RECT  2.16 20.655 21.6 20.925 ;
     RECT  2.16 21.195 21.6 21.465 ;
     RECT  2.16 21.735 21.6 22.005 ;
     RECT  2.16 22.275 21.6 22.545 ;
     RECT  2.16 22.815 21.6 23.085 ;
     RECT  2.16 23.355 21.6 23.625 ;
     RECT  2.16 23.895 21.6 24.165 ;
     RECT  2.16 24.435 21.6 24.705 ;
     RECT  2.16 24.975 21.6 25.245 ;
     RECT  2.16 25.515 21.6 25.785 ;
     RECT  2.16 26.055 21.6 26.325 ;
     RECT  2.16 26.595 21.6 26.865 ;
     RECT  2.16 27.135 21.6 27.405 ;
     RECT  2.16 27.675 21.6 27.945 ;
    LAYER M1 ;
     RECT  2.16 2.151 21.6 28.089 ;
    LAYER M2 ;
     RECT  0.031 27.576 0.103 27.594 ;
     RECT  0.103 27.306 0.131 27.594 ;
     RECT  0.103 12.456 0.139 13.464 ;
     RECT  0.103 17.586 0.139 18.414 ;
     RECT  0.103 23.328 0.139 23.346 ;
     RECT  0.031 26.37 0.139 26.388 ;
     RECT  0.131 27.306 0.139 27.324 ;
     RECT  0.103 2.196 0.175 2.214 ;
     RECT  0.103 4.734 0.175 4.752 ;
     RECT  0.103 9.666 0.175 9.684 ;
     RECT  0.103 10.746 0.175 11.394 ;
     RECT  0.139 12.294 0.175 13.464 ;
     RECT  0.103 14.616 0.175 15.282 ;
     RECT  0.103 22.014 0.175 22.032 ;
     RECT  0.139 22.788 0.175 23.346 ;
     RECT  0.103 24.174 0.175 25.542 ;
     RECT  0.175 2.196 0.211 2.592 ;
     RECT  0.103 3.384 0.211 3.942 ;
     RECT  0.175 10.746 0.211 15.282 ;
     RECT  0.103 5.886 0.427 5.904 ;
     RECT  0.103 6.786 0.427 6.804 ;
     RECT  0.175 21.636 0.427 25.542 ;
     RECT  0.175 8.946 0.499 9.684 ;
     RECT  0.211 10.71 0.499 15.282 ;
     RECT  0.139 17.586 0.499 19.062 ;
     RECT  0.427 21.546 0.499 25.542 ;
     RECT  0.211 2.196 0.535 3.942 ;
     RECT  0.175 4.734 0.535 5.094 ;
     RECT  0.427 5.886 0.535 6.804 ;
     RECT  0.391 7.668 0.535 7.686 ;
     RECT  0.499 17.226 0.535 19.062 ;
     RECT  0.499 21.51 0.535 25.542 ;
     RECT  0.139 26.37 0.535 27.324 ;
     RECT  0.535 2.196 1.147 7.686 ;
     RECT  0.535 21.204 1.147 27.324 ;
     RECT  1.147 2.196 2.16 7.758 ;
     RECT  0.499 8.784 2.16 9.684 ;
     RECT  0.499 10.71 2.16 15.354 ;
     RECT  0.535 17.226 2.16 19.368 ;
     RECT  1.147 21.204 2.16 27.864 ;
     RECT  2.16 2.151 2.299 28.089 ;
     RECT  2.299 1.962 4.163 28.089 ;
     RECT  4.163 2.034 5.855 28.089 ;
     RECT  5.855 2.106 7.187 28.089 ;
     RECT  7.187 2.151 16.807 28.089 ;
     RECT  16.807 2.106 16.915 28.089 ;
     RECT  16.915 1.998 17.527 28.089 ;
     RECT  17.527 1.836 18.931 28.089 ;
     RECT  18.931 1.728 21.011 28.089 ;
     RECT  21.011 1.764 21.299 28.089 ;
     RECT  21.299 1.8 21.6 28.089 ;
     RECT  21.6 1.8 21.659 27.936 ;
     RECT  21.659 1.8 22.271 14.508 ;
     RECT  22.271 1.8 22.307 9.306 ;
     RECT  22.271 10.17 22.307 14.508 ;
     RECT  21.659 15.3 22.307 27.936 ;
     RECT  22.307 16.614 22.343 22.536 ;
     RECT  22.307 10.368 22.531 14.508 ;
     RECT  22.307 15.3 22.531 15.858 ;
     RECT  22.531 10.368 22.595 15.858 ;
     RECT  22.595 14.148 22.667 15.318 ;
     RECT  22.307 1.836 22.703 9.306 ;
     RECT  22.595 10.368 22.703 13.356 ;
     RECT  22.667 14.49 22.703 15.318 ;
     RECT  22.703 1.836 22.739 9.072 ;
     RECT  22.703 10.368 22.739 10.656 ;
     RECT  22.703 11.448 22.739 13.086 ;
     RECT  22.343 16.65 22.739 22.536 ;
     RECT  22.307 23.328 22.739 25.236 ;
     RECT  22.307 26.028 22.739 27.936 ;
     RECT  22.703 14.49 22.775 14.508 ;
     RECT  22.739 6.048 22.811 7.254 ;
     RECT  22.739 8.442 22.811 9.072 ;
     RECT  22.739 10.368 22.811 10.386 ;
     RECT  22.739 16.65 22.811 17.478 ;
     RECT  22.739 18.54 22.811 21.996 ;
     RECT  22.739 23.328 22.811 23.688 ;
     RECT  22.739 24.48 22.811 24.804 ;
     RECT  22.739 26.028 22.811 26.082 ;
     RECT  22.739 26.838 22.811 27.666 ;
     RECT  22.739 11.52 22.847 12.312 ;
     RECT  22.703 15.3 22.847 15.318 ;
     RECT  22.811 17.082 22.847 17.478 ;
     RECT  22.811 18.54 22.847 20.214 ;
     RECT  22.811 21.24 22.847 21.996 ;
     RECT  22.811 23.328 22.847 23.346 ;
     RECT  22.811 24.48 22.847 24.498 ;
     RECT  22.811 26.028 22.847 26.046 ;
     RECT  22.847 11.556 22.883 12.312 ;
     RECT  22.739 1.836 23.567 4.788 ;
     RECT  22.847 18.666 23.575 19.224 ;
     RECT  23.567 3.618 23.603 4.752 ;
     RECT  22.847 17.082 23.603 17.406 ;
     RECT  22.811 26.838 23.603 27.234 ;
     RECT  23.567 1.836 23.639 2.826 ;
     RECT  23.603 3.618 23.639 3.708 ;
     RECT  23.603 4.464 23.639 4.752 ;
     RECT  22.811 6.696 23.639 7.254 ;
     RECT  22.883 12.024 23.639 12.312 ;
     RECT  23.575 18.468 23.639 19.224 ;
     RECT  23.639 2.304 23.675 2.322 ;
     RECT  23.639 3.618 23.675 3.636 ;
     RECT  23.639 4.734 23.675 4.752 ;
     RECT  23.639 6.696 23.675 6.714 ;
     RECT  22.811 9.054 23.675 9.072 ;
     RECT  23.639 12.024 23.675 12.114 ;
     RECT  23.603 17.388 23.675 17.406 ;
     RECT  23.639 18.468 23.675 19.098 ;
     RECT  22.847 20.16 23.675 20.178 ;
     RECT  23.603 27.216 23.675 27.234 ;
     RECT  23.675 18.666 23.711 18.684 ;
     RECT  22.847 21.438 23.711 21.924 ;
     RECT  23.647 10.134 23.747 10.152 ;
     RECT  23.675 12.024 23.747 12.042 ;
     RECT  23.575 15.336 23.747 15.354 ;
     RECT  23.711 21.438 23.747 21.456 ;
    LAYER M3 ;
     RECT  21.06 0.811 21.078 1.003 ;
     RECT  22.212 0.907 22.23 1.003 ;
     RECT  21.06 1.003 22.23 1.195 ;
     RECT  23.652 0.715 23.67 1.387 ;
     RECT  23.616 1.387 23.67 1.483 ;
     RECT  21.06 1.195 22.806 1.723 ;
     RECT  23.58 1.483 23.67 1.771 ;
     RECT  18.936 1.723 18.954 1.795 ;
     RECT  19.872 1.759 19.89 1.795 ;
     RECT  18.936 1.795 19.89 1.876 ;
     RECT  18.936 1.876 20.106 1.921 ;
     RECT  20.988 1.723 22.806 1.921 ;
     RECT  17.532 1.831 17.55 1.993 ;
     RECT  2.304 1.957 2.322 2.029 ;
     RECT  16.92 1.993 17.55 2.065 ;
     RECT  18.936 1.921 22.806 2.065 ;
     RECT  2.304 2.029 2.862 2.101 ;
     RECT  16.92 2.065 22.806 2.101 ;
     RECT  7.164 2.101 7.182 2.143 ;
     RECT  4.14 1.957 4.158 2.191 ;
     RECT  5.832 2.029 5.85 2.191 ;
     RECT  13.215 2.143 13.305 2.227 ;
     RECT  5.292 2.191 5.85 2.263 ;
     RECT  7.164 2.143 7.905 2.263 ;
     RECT  2.304 2.101 3.114 2.299 ;
     RECT  4.14 2.191 4.338 2.299 ;
     RECT  5.112 2.263 7.905 2.299 ;
     RECT  16.812 2.101 22.806 2.299 ;
     RECT  23.544 1.771 23.67 2.327 ;
     RECT  11.016 2.299 11.106 2.335 ;
     RECT  13.215 2.227 13.698 2.347 ;
     RECT  10.872 2.335 11.106 2.371 ;
     RECT  2.304 2.299 7.905 2.413 ;
     RECT  10.836 2.371 11.106 2.461 ;
     RECT  14.832 2.299 15.21 2.488 ;
     RECT  9.072 2.461 9.09 2.497 ;
     RECT  13.215 2.347 13.77 2.497 ;
     RECT  14.832 2.488 15.246 2.497 ;
     RECT  16.092 2.299 22.806 2.497 ;
     RECT  23.544 2.327 23.634 2.497 ;
     RECT  10.404 2.461 11.646 2.533 ;
     RECT  0.108 2.191 0.126 2.539 ;
     RECT  8.82 2.497 9.09 2.569 ;
     RECT  13.215 2.497 15.246 2.569 ;
     RECT  0.108 2.539 0.342 2.573 ;
     RECT  8.82 2.569 9.126 2.605 ;
     RECT  16.092 2.497 23.634 2.605 ;
     RECT  10.404 2.533 11.97 2.641 ;
     RECT  13.104 2.569 15.246 2.641 ;
     RECT  2.304 2.413 8.097 2.731 ;
     RECT  8.82 2.605 9.522 2.731 ;
     RECT  13.068 2.641 15.246 2.731 ;
     RECT  16.056 2.605 23.634 2.731 ;
     RECT  2.304 2.731 9.522 2.803 ;
     RECT  10.26 2.641 12.294 2.827 ;
     RECT  13.068 2.731 23.634 2.827 ;
     RECT  2.268 2.803 9.522 2.911 ;
     RECT  10.26 2.827 23.634 2.911 ;
     RECT  2.268 2.911 23.634 2.939 ;
     RECT  2.304 2.939 23.634 3.173 ;
     RECT  22.212 3.173 23.634 3.307 ;
     RECT  0.144 2.573 0.342 3.341 ;
     RECT  0.144 3.341 0.27 3.379 ;
     RECT  22.212 3.307 23.67 3.533 ;
     RECT  2.304 3.173 21.402 3.979 ;
     RECT  22.212 3.533 22.842 3.979 ;
     RECT  2.304 3.979 22.842 4.189 ;
     RECT  2.268 4.189 22.842 4.301 ;
     RECT  2.304 4.301 22.842 4.459 ;
     RECT  23.58 3.533 23.67 4.459 ;
     RECT  0.108 3.379 0.27 4.531 ;
     RECT  0.108 4.531 0.558 4.589 ;
     RECT  2.304 4.459 23.67 4.757 ;
     RECT  2.304 4.757 23.562 4.793 ;
     RECT  2.304 4.793 22.842 4.973 ;
     RECT  0.108 4.589 0.342 5.341 ;
     RECT  2.304 4.973 22.734 5.809 ;
     RECT  2.268 5.809 22.734 5.899 ;
     RECT  2.268 5.899 22.806 5.933 ;
     RECT  23.652 5.707 23.67 5.995 ;
     RECT  0.108 5.341 0.558 6.091 ;
     RECT  0.108 6.091 0.666 6.221 ;
     RECT  2.304 5.933 22.806 6.221 ;
     RECT  22.176 6.221 22.806 6.647 ;
     RECT  2.304 6.221 21.258 6.961 ;
     RECT  22.176 6.647 22.734 7.051 ;
     RECT  0.108 6.221 0.522 7.085 ;
     RECT  23.616 5.995 23.67 7.259 ;
     RECT  2.304 6.961 21.402 7.393 ;
     RECT  22.14 7.051 22.734 7.393 ;
     RECT  0.396 7.085 0.522 7.501 ;
     RECT  0.396 7.501 0.558 7.663 ;
     RECT  0.396 7.663 1.17 7.763 ;
     RECT  2.304 7.393 22.734 7.799 ;
     RECT  2.304 7.799 21.69 8.041 ;
     RECT  2.232 8.041 21.69 8.195 ;
     RECT  22.716 7.799 22.734 8.395 ;
     RECT  2.268 8.195 21.69 8.465 ;
     RECT  22.716 8.395 22.806 8.465 ;
     RECT  0.396 7.763 0.558 8.539 ;
     RECT  2.304 8.465 21.69 8.587 ;
     RECT  2.304 8.587 21.726 8.683 ;
     RECT  22.716 8.465 22.734 8.77 ;
     RECT  0.144 8.539 0.558 8.813 ;
     RECT  22.68 8.77 22.734 9.041 ;
     RECT  2.304 8.683 21.762 9.067 ;
     RECT  22.68 9.041 22.698 9.067 ;
     RECT  23.652 7.259 23.67 9.077 ;
     RECT  0.18 8.813 0.558 9.197 ;
     RECT  0.18 9.197 0.522 9.661 ;
     RECT  0.108 9.661 0.522 9.677 ;
     RECT  2.304 9.067 22.698 9.931 ;
     RECT  23.652 10.12 23.67 10.129 ;
     RECT  23.652 10.129 23.742 10.157 ;
     RECT  2.304 9.931 22.806 10.391 ;
     RECT  2.304 10.391 22.734 10.589 ;
     RECT  0.108 9.677 0.126 10.705 ;
     RECT  0.108 10.705 0.234 10.939 ;
     RECT  0.108 10.939 0.486 11.209 ;
     RECT  0.108 11.209 0.522 11.281 ;
     RECT  2.34 10.589 22.734 11.467 ;
     RECT  2.304 11.467 22.734 11.515 ;
     RECT  2.304 11.515 22.842 11.551 ;
     RECT  0.108 11.281 0.558 11.597 ;
     RECT  2.304 11.551 22.878 11.597 ;
     RECT  0.108 11.597 0.522 11.693 ;
     RECT  2.304 11.597 22.842 11.885 ;
     RECT  23.724 10.157 23.742 12.043 ;
     RECT  23.652 12.043 23.742 12.047 ;
     RECT  23.652 12.047 23.67 12.119 ;
     RECT  23.616 12.139 23.634 12.317 ;
     RECT  0.108 11.693 0.486 12.631 ;
     RECT  2.304 11.885 22.266 12.715 ;
     RECT  0.108 12.631 0.522 12.829 ;
     RECT  2.304 12.715 22.734 13.091 ;
     RECT  2.304 13.091 22.698 14.485 ;
     RECT  2.304 14.485 22.77 14.989 ;
     RECT  23.652 13.387 23.67 15.115 ;
     RECT  2.268 14.989 22.77 15.149 ;
     RECT  2.304 15.149 22.77 15.295 ;
     RECT  23.616 15.115 23.67 15.307 ;
     RECT  23.58 15.307 23.67 15.331 ;
     RECT  0.108 12.829 0.558 15.533 ;
     RECT  2.304 15.295 22.842 15.691 ;
     RECT  23.58 15.331 23.742 15.691 ;
     RECT  0.216 15.533 0.558 15.725 ;
     RECT  0.216 15.725 0.522 16.013 ;
     RECT  2.304 15.691 23.742 16.171 ;
     RECT  0.216 16.013 0.234 16.301 ;
     RECT  2.268 16.171 23.742 16.397 ;
     RECT  2.268 16.397 22.806 16.979 ;
     RECT  0.504 17.221 0.522 17.419 ;
     RECT  2.304 16.979 22.806 17.455 ;
     RECT  23.544 16.397 23.742 17.455 ;
     RECT  0.504 17.419 0.558 17.515 ;
     RECT  0.324 17.515 0.558 17.581 ;
     RECT  0.108 17.581 0.558 17.933 ;
     RECT  0.108 17.933 0.522 18.125 ;
     RECT  2.304 17.455 23.742 18.379 ;
     RECT  2.268 18.379 23.742 18.527 ;
     RECT  0.108 18.125 0.486 18.605 ;
     RECT  2.304 18.527 23.742 18.689 ;
     RECT  2.304 18.689 22.842 18.797 ;
     RECT  0.108 18.605 0.342 19.345 ;
     RECT  0.108 19.345 0.558 19.469 ;
     RECT  0.144 19.469 0.558 19.565 ;
     RECT  2.304 18.797 22.698 19.885 ;
     RECT  0.216 19.565 0.558 19.949 ;
     RECT  0.216 19.949 0.342 20.141 ;
     RECT  2.304 19.885 22.842 20.251 ;
     RECT  0.216 20.141 0.234 20.285 ;
     RECT  2.268 20.251 22.842 20.333 ;
     RECT  23.58 18.689 23.742 20.621 ;
     RECT  2.268 20.333 22.806 21.235 ;
     RECT  2.268 21.235 22.842 21.299 ;
     RECT  0.54 21.199 0.558 21.355 ;
     RECT  23.688 20.621 23.742 21.461 ;
     RECT  2.304 21.299 22.842 21.505 ;
     RECT  2.304 21.505 22.878 21.581 ;
     RECT  0.324 21.355 0.558 21.631 ;
     RECT  23.688 21.461 23.706 21.739 ;
     RECT  23.652 21.739 23.706 21.803 ;
     RECT  23.688 21.803 23.706 21.929 ;
     RECT  0.18 21.631 0.558 22.009 ;
     RECT  2.304 21.581 22.842 22.045 ;
     RECT  2.268 22.045 22.842 22.157 ;
     RECT  2.268 22.157 22.734 22.541 ;
     RECT  2.268 22.541 22.518 22.733 ;
     RECT  2.304 22.733 22.518 23.323 ;
     RECT  2.304 23.323 22.842 23.405 ;
     RECT  2.304 23.405 22.806 23.693 ;
     RECT  2.304 23.693 22.77 24.475 ;
     RECT  0.108 22.009 0.558 25.051 ;
     RECT  2.304 24.475 22.842 25.079 ;
     RECT  22.212 25.079 22.842 25.133 ;
     RECT  2.304 25.079 21.402 25.591 ;
     RECT  22.248 25.133 22.842 26.093 ;
     RECT  1.98 25.591 21.402 26.095 ;
     RECT  1.98 26.095 21.726 26.285 ;
     RECT  22.716 26.093 22.842 26.285 ;
     RECT  0.108 25.051 0.846 26.365 ;
     RECT  12.276 26.285 21.726 26.393 ;
     RECT  23.58 26.731 23.598 26.861 ;
     RECT  1.98 26.285 11.538 26.869 ;
     RECT  12.312 26.393 21.726 27.019 ;
     RECT  22.716 26.285 22.806 27.019 ;
     RECT  12.312 27.019 22.806 27.167 ;
     RECT  22.716 27.167 22.806 27.175 ;
     RECT  23.652 26.923 23.67 27.239 ;
     RECT  22.716 27.175 22.842 27.245 ;
     RECT  1.656 26.869 11.538 27.301 ;
     RECT  12.312 27.167 21.834 27.301 ;
     RECT  0.036 26.365 0.846 27.599 ;
     RECT  1.656 27.301 21.834 27.599 ;
     RECT  16.308 27.599 21.834 27.629 ;
     RECT  16.308 27.629 19.098 27.671 ;
     RECT  22.716 27.245 22.806 27.671 ;
     RECT  1.656 27.599 10.242 27.679 ;
     RECT  11.844 27.599 15.138 27.707 ;
     RECT  20.196 27.629 21.834 27.707 ;
     RECT  1.62 27.679 10.242 27.743 ;
     RECT  11.844 27.707 14.922 27.743 ;
     RECT  16.308 27.671 19.062 27.743 ;
     RECT  20.196 27.707 21.69 27.743 ;
     RECT  1.62 27.743 9.99 27.773 ;
     RECT  20.196 27.743 21.654 27.779 ;
     RECT  12.384 27.743 14.382 27.827 ;
     RECT  16.308 27.743 18.897 27.827 ;
     RECT  0.108 27.599 0.846 27.841 ;
     RECT  1.62 27.773 8.982 27.841 ;
     RECT  0.108 27.841 8.982 27.869 ;
     RECT  12.384 27.827 13.305 27.869 ;
     RECT  16.308 27.827 18.705 27.869 ;
     RECT  20.268 27.779 21.114 27.869 ;
     RECT  4.644 27.869 8.982 27.905 ;
     RECT  16.308 27.869 17.442 27.905 ;
     RECT  18.216 27.869 18.705 27.905 ;
     RECT  20.268 27.869 21.006 27.905 ;
     RECT  5.148 27.905 5.634 27.941 ;
     RECT  6.588 27.905 6.678 27.941 ;
     RECT  9.9 27.773 9.99 27.941 ;
     RECT  14.04 27.827 14.382 27.941 ;
     RECT  16.308 27.905 17.046 27.941 ;
     RECT  18.36 27.905 18.705 27.941 ;
     RECT  20.988 27.905 21.006 27.941 ;
     RECT  22.716 27.671 22.734 27.941 ;
     RECT  7.815 27.905 8.982 27.965 ;
     RECT  9.972 27.941 9.99 27.965 ;
     RECT  12.744 27.869 13.305 27.965 ;
     RECT  14.364 27.941 14.382 27.965 ;
     RECT  17.028 27.941 17.046 27.965 ;
     RECT  7.815 27.965 8.694 27.977 ;
     RECT  0.108 27.869 3.834 28.013 ;
     RECT  7.815 27.977 8.55 28.049 ;
     RECT  7.815 28.049 7.905 28.097 ;
     RECT  13.215 27.965 13.305 28.097 ;
     RECT  18.615 27.941 18.705 28.097 ;
     RECT  0.324 28.013 3.042 28.109 ;
     RECT  0.828 28.109 3.042 28.301 ;
     RECT  0.828 28.301 3.006 28.397 ;
     RECT  0.828 28.397 2.934 28.493 ;
     RECT  1.152 28.493 2.934 28.781 ;
     RECT  3.816 28.013 3.834 28.877 ;
     RECT  1.152 28.781 1.71 28.973 ;
     RECT  2.556 28.781 2.934 29.069 ;
     RECT  2.916 29.069 2.934 29.165 ;
     RECT  1.152 28.973 1.674 29.261 ;
     RECT  1.62 29.261 1.674 29.357 ;
     RECT  1.62 29.357 1.638 29.453 ;
    LAYER M4 ;
     RECT  0.06 2.256 1.649 29.448 ;
     RECT  1.649 2.256 1.685 29.352 ;
     RECT  1.685 2.256 2.408 29.16 ;
     RECT  2.408 2.148 2.512 29.16 ;
     RECT  2.512 2.256 2.729 29.16 ;
     RECT  2.729 2.352 2.873 29.16 ;
     RECT  2.873 2.496 2.945 29.16 ;
     RECT  2.945 2.496 3.269 28.872 ;
     RECT  3.269 20.304 3.845 28.872 ;
     RECT  3.269 2.496 4.345 19.32 ;
     RECT  3.845 20.304 4.345 27.912 ;
     RECT  4.345 2.496 4.421 27.912 ;
     RECT  4.421 2.736 4.673 27.912 ;
     RECT  4.673 2.784 5.609 27.912 ;
     RECT  5.609 2.784 6.001 13.896 ;
     RECT  6.001 2.592 6.613 13.896 ;
     RECT  6.613 2.496 6.757 13.896 ;
     RECT  5.609 15.216 6.757 27.912 ;
     RECT  6.757 2.496 7.808 27.912 ;
     RECT  7.808 2.148 7.912 28.092 ;
     RECT  7.912 2.418 8.104 27.912 ;
     RECT  8.104 2.736 8.953 27.912 ;
     RECT  8.953 2.736 9.317 27.96 ;
     RECT  9.317 20.352 10.001 27.96 ;
     RECT  9.317 2.736 10.501 19.368 ;
     RECT  10.001 20.352 10.501 27.528 ;
     RECT  10.501 2.736 10.901 27.528 ;
     RECT  10.901 2.736 12.553 27.48 ;
     RECT  12.553 2.736 12.733 27.624 ;
     RECT  12.733 2.736 13.208 27.96 ;
     RECT  13.208 2.148 13.312 28.092 ;
     RECT  13.312 2.304 14.105 27.96 ;
     RECT  14.105 26.784 14.393 27.96 ;
     RECT  14.105 2.304 15.221 25.752 ;
     RECT  15.221 2.496 15.257 25.752 ;
     RECT  15.257 2.736 15.545 25.752 ;
     RECT  14.393 26.784 15.869 27.624 ;
     RECT  15.869 26.832 16.337 27.624 ;
     RECT  15.545 2.736 16.373 25.608 ;
     RECT  16.337 26.976 16.841 27.624 ;
     RECT  16.841 27.072 16.873 27.624 ;
     RECT  16.873 27.072 16.945 27.816 ;
     RECT  16.945 27.072 16.988 27.864 ;
     RECT  16.373 2.736 17.053 17.4 ;
     RECT  16.988 27.072 17.075 27.96 ;
     RECT  16.373 18.672 17.129 25.608 ;
     RECT  17.053 2.544 17.273 17.4 ;
     RECT  17.273 14.112 17.773 17.4 ;
     RECT  17.129 18.816 18.053 25.608 ;
     RECT  17.075 27.072 18.053 27.864 ;
     RECT  17.773 14.112 18.277 17.736 ;
     RECT  18.053 18.816 18.277 27.864 ;
     RECT  17.273 2.544 18.608 13.128 ;
     RECT  18.277 14.112 18.608 27.864 ;
     RECT  18.608 2.148 18.712 28.092 ;
     RECT  18.712 2.256 18.904 27.822 ;
     RECT  18.904 10.608 19.541 25.176 ;
     RECT  19.541 10.608 19.865 12.072 ;
     RECT  19.541 13.536 19.897 25.176 ;
     RECT  19.865 10.608 19.933 11.784 ;
     RECT  18.904 26.784 20.005 27.624 ;
     RECT  20.005 26.64 20.185 27.624 ;
     RECT  19.897 13.536 20.293 25.464 ;
     RECT  20.185 26.64 20.293 27.768 ;
     RECT  20.293 13.536 20.297 27.768 ;
     RECT  19.933 10.176 20.369 11.784 ;
     RECT  18.904 2.256 20.437 9.096 ;
     RECT  20.297 13.584 20.581 27.768 ;
     RECT  20.369 10.704 20.876 11.784 ;
     RECT  20.581 13.584 20.977 27.816 ;
     RECT  20.876 10.704 21.517 11.976 ;
     RECT  21.049 0.816 21.553 0.84 ;
     RECT  20.437 2.256 21.553 9.672 ;
     RECT  21.517 10.704 21.625 12.552 ;
     RECT  20.977 13.584 21.625 27.912 ;
     RECT  21.553 0.816 21.805 9.672 ;
     RECT  21.625 10.704 21.805 27.912 ;
     RECT  21.805 0.816 23.641 27.912 ;
     RECT  23.641 0.72 23.724 27.912 ;
    LAYER M5 ;
     RECT  2.4 2.137 2.52 2.151 ;
     RECT  7.8 2.137 7.92 2.151 ;
     RECT  13.2 2.137 13.32 2.151 ;
     RECT  18.6 2.137 18.72 2.151 ;
     RECT  13.2 2.151 13.512 2.581 ;
     RECT  0.144 3.157 0.168 3.347 ;
     RECT  14.784 3.061 14.808 4.019 ;
     RECT  21.648 2.917 21.672 4.019 ;
     RECT  20.496 3.397 20.52 4.115 ;
     RECT  13.2 2.581 13.608 4.357 ;
     RECT  7.8 2.151 8.112 4.693 ;
     RECT  18.6 2.151 18.912 5.317 ;
     RECT  13.104 4.357 13.608 5.507 ;
     RECT  6.96 4.693 8.112 5.603 ;
     RECT  0.144 5.509 0.168 5.699 ;
     RECT  12.096 5.125 12.12 5.747 ;
     RECT  18.6 5.317 19.56 6.131 ;
     RECT  7.392 5.603 8.112 6.323 ;
     RECT  13.2 5.507 13.608 6.853 ;
     RECT  13.2 6.853 13.752 6.995 ;
     RECT  20.496 6.565 20.52 7.141 ;
     RECT  7.8 6.323 8.112 7.381 ;
     RECT  11.664 6.277 11.688 7.381 ;
     RECT  20.448 7.141 20.52 7.475 ;
     RECT  11.28 7.381 11.688 7.667 ;
     RECT  13.2 6.995 13.656 7.763 ;
     RECT  7.8 7.381 8.232 7.909 ;
     RECT  18.6 6.131 19.032 7.909 ;
     RECT  17.664 7.909 19.032 7.955 ;
     RECT  13.2 7.763 13.608 7.957 ;
     RECT  15.936 6.757 15.96 8.003 ;
     RECT  20.448 7.475 20.472 8.003 ;
     RECT  7.8 7.909 8.808 8.533 ;
     RECT  13.104 7.957 13.608 8.579 ;
     RECT  0.144 8.821 0.168 9.011 ;
     RECT  11.28 7.667 11.304 9.299 ;
     RECT  17.664 7.955 18.912 9.299 ;
     RECT  7.056 8.533 9.096 9.539 ;
     RECT  13.2 8.579 13.608 10.213 ;
     RECT  15.456 8.821 15.48 10.307 ;
     RECT  7.056 9.539 8.232 10.405 ;
     RECT  12.912 10.213 13.608 10.643 ;
     RECT  12.912 10.643 13.512 10.645 ;
     RECT  6.864 10.405 8.232 11.125 ;
     RECT  18.6 9.299 18.912 11.365 ;
     RECT  20.448 9.589 20.472 11.365 ;
     RECT  18.6 11.365 20.472 11.413 ;
     RECT  18.192 11.413 20.472 11.461 ;
     RECT  6.816 11.125 8.232 11.699 ;
     RECT  9.936 11.173 9.96 11.987 ;
     RECT  6.816 11.699 8.112 12.083 ;
     RECT  14.544 11.461 14.568 12.181 ;
     RECT  14.544 12.181 14.664 12.277 ;
     RECT  18.192 11.461 21.096 12.709 ;
     RECT  7.8 12.083 8.112 12.901 ;
     RECT  10.128 12.757 10.152 13.043 ;
     RECT  14.544 12.277 14.76 13.045 ;
     RECT  14.544 13.045 15.384 13.091 ;
     RECT  18 12.709 21.096 13.715 ;
     RECT  11.568 12.085 11.592 13.811 ;
     RECT  7.8 12.901 8.952 13.861 ;
     RECT  7.8 13.861 9.048 14.003 ;
     RECT  18 13.715 20.952 14.051 ;
     RECT  18 14.051 20.472 14.147 ;
     RECT  14.688 13.091 15.384 14.195 ;
     RECT  12.72 10.645 13.512 14.773 ;
     RECT  7.8 14.003 8.952 14.915 ;
     RECT  18.6 14.147 20.472 15.061 ;
     RECT  18.6 15.061 21.288 15.205 ;
     RECT  22.464 14.629 22.488 15.205 ;
     RECT  9.12 15.253 9.144 15.395 ;
     RECT  12.72 14.773 13.656 15.589 ;
     RECT  12 15.589 13.656 15.779 ;
     RECT  13.056 15.779 13.656 16.259 ;
     RECT  10.656 16.261 10.68 16.451 ;
     RECT  18.6 15.205 22.488 16.499 ;
     RECT  15.36 14.195 15.384 17.077 ;
     RECT  16.944 16.213 16.968 17.077 ;
     RECT  5.808 17.077 5.832 17.219 ;
     RECT  18.6 16.499 20.376 17.989 ;
     RECT  10.512 16.501 10.536 18.133 ;
     RECT  7.8 14.915 8.112 18.181 ;
     RECT  18.432 17.989 20.376 18.181 ;
     RECT  21.888 16.499 22.488 18.181 ;
     RECT  12 15.779 12.024 18.659 ;
     RECT  10.512 18.133 10.968 18.707 ;
     RECT  18.432 18.181 22.488 18.851 ;
     RECT  18.432 18.851 20.472 18.853 ;
     RECT  15.36 17.077 16.968 18.997 ;
     RECT  18.288 18.853 20.472 18.997 ;
     RECT  15.36 18.997 20.472 19.091 ;
     RECT  9.504 18.949 9.528 19.139 ;
     RECT  15.36 19.091 20.376 19.189 ;
     RECT  14.784 19.189 20.376 19.331 ;
     RECT  7.8 18.181 8.232 19.571 ;
     RECT  15.408 19.331 20.376 19.715 ;
     RECT  0.144 17.461 0.168 19.859 ;
     RECT  18.096 19.715 20.376 20.101 ;
     RECT  21.648 18.851 22.488 20.101 ;
     RECT  10.512 18.707 10.536 20.339 ;
     RECT  7.8 19.571 8.112 20.341 ;
     RECT  15.408 19.715 16.968 20.579 ;
     RECT  18.096 20.101 22.488 20.819 ;
     RECT  16.128 20.579 16.968 20.867 ;
     RECT  7.056 20.341 8.112 20.915 ;
     RECT  16.512 20.867 16.968 20.963 ;
     RECT  13.056 16.259 13.512 21.013 ;
     RECT  11.568 20.869 11.592 21.443 ;
     RECT  21.888 20.819 22.488 21.731 ;
     RECT  18.096 20.819 20.616 21.779 ;
     RECT  0.144 21.301 0.168 22.019 ;
     RECT  21.888 21.731 21.912 22.259 ;
     RECT  7.8 20.915 8.112 22.885 ;
     RECT  18.096 21.779 20.568 22.931 ;
     RECT  18.096 22.931 20.472 22.979 ;
     RECT  18.096 22.979 20.376 23.027 ;
     RECT  0.144 23.125 0.168 23.315 ;
     RECT  18.096 23.027 19.848 23.987 ;
     RECT  7.68 22.885 8.112 24.227 ;
     RECT  9.84 22.549 9.864 24.515 ;
     RECT  16.944 20.963 16.968 24.901 ;
     RECT  18.096 23.987 19.464 25.045 ;
     RECT  21.648 23.749 21.672 25.045 ;
     RECT  18.096 25.045 21.672 25.139 ;
     RECT  16.512 24.901 16.968 25.187 ;
     RECT  18.096 25.139 21.288 25.187 ;
     RECT  20.304 25.187 21.288 25.523 ;
     RECT  20.304 25.523 20.328 25.715 ;
     RECT  12.816 21.013 13.512 25.763 ;
     RECT  7.8 24.227 8.112 26.197 ;
     RECT  18.096 25.187 18.912 26.243 ;
     RECT  11.664 22.357 11.688 26.291 ;
     RECT  2.4 2.151 2.712 26.293 ;
     RECT  2.4 26.293 2.856 26.579 ;
     RECT  7.584 26.197 8.112 26.819 ;
     RECT  14.88 25.285 14.904 26.819 ;
     RECT  18.192 26.243 18.912 27.395 ;
     RECT  2.4 26.579 2.712 27.733 ;
     RECT  16.944 25.187 16.968 27.925 ;
     RECT  2.4 27.733 2.808 27.971 ;
     RECT  2.4 27.971 2.712 28.089 ;
     RECT  7.8 26.819 8.112 28.089 ;
     RECT  13.2 25.763 13.512 28.089 ;
     RECT  18.6 27.395 18.912 28.089 ;
     RECT  2.4 28.089 2.52 28.103 ;
     RECT  7.8 28.089 7.92 28.103 ;
     RECT  13.2 28.089 13.32 28.103 ;
     RECT  18.6 28.089 18.72 28.103 ;
     RECT  16.944 27.925 17.064 30.224 ;
     RECT  13.608 3.061 14.784 4.019 ;
     RECT  20.52 3.397 21.648 4.019 ;
     RECT  12.12 5.125 13.104 5.507 ;
     RECT  12.12 5.507 13.2 5.747 ;
     RECT  12.096 5.747 13.2 6.277 ;
     RECT  19.032 6.131 19.56 6.565 ;
     RECT  11.688 6.277 13.2 7.667 ;
     RECT  19.032 6.565 20.496 7.141 ;
     RECT  19.032 7.141 20.448 7.955 ;
     RECT  13.104 7.667 13.2 7.957 ;
     RECT  13.512 10.643 13.608 11.461 ;
     RECT  13.512 11.461 14.544 13.091 ;
     RECT  8.112 11.699 8.232 12.901 ;
     RECT  9.936 11.987 9.96 12.757 ;
     RECT  11.592 12.085 12.72 13.811 ;
     RECT  9.936 12.757 10.128 12.901 ;
     RECT  10.152 12.757 11.568 13.043 ;
     RECT  8.952 12.901 10.128 13.043 ;
     RECT  8.952 13.043 9.048 13.861 ;
     RECT  13.512 13.091 14.688 14.195 ;
     RECT  20.952 13.715 21.096 14.051 ;
     RECT  8.952 14.003 9.048 14.915 ;
     RECT  20.472 14.051 21.096 14.629 ;
     RECT  13.512 14.195 13.656 14.773 ;
     RECT  20.472 14.629 22.464 15.061 ;
     RECT  8.112 14.915 9.048 15.253 ;
     RECT  21.288 15.061 22.464 15.205 ;
     RECT  8.112 15.253 9.12 15.395 ;
     RECT  12.024 15.779 13.056 18.659 ;
     RECT  10.68 16.261 12 16.451 ;
     RECT  10.656 16.451 12 16.501 ;
     RECT  20.376 16.499 21.888 18.181 ;
     RECT  10.536 16.501 12 18.133 ;
     RECT  16.968 17.989 18.432 18.853 ;
     RECT  10.968 18.133 12 18.659 ;
     RECT  20.472 18.851 21.648 19.091 ;
     RECT  16.968 18.853 18.288 18.997 ;
     RECT  8.232 18.949 9.504 19.139 ;
     RECT  9.528 18.949 10.512 19.139 ;
     RECT  20.376 19.091 21.648 20.101 ;
     RECT  13.512 19.189 14.784 19.331 ;
     RECT  16.968 19.715 18.096 26.243 ;
     RECT  0.144 19.859 0.168 21.301 ;
     RECT  20.616 20.819 21.888 21.779 ;
     RECT  11.592 20.869 13.056 21.013 ;
     RECT  11.592 21.013 12.816 21.443 ;
     RECT  11.664 21.443 12.816 22.357 ;
     RECT  20.568 21.779 21.888 22.259 ;
     RECT  0.144 22.019 0.168 23.125 ;
     RECT  20.568 22.259 21.672 22.931 ;
     RECT  11.688 22.357 12.816 25.763 ;
     RECT  20.472 22.931 21.672 22.979 ;
     RECT  20.376 22.979 21.672 23.027 ;
     RECT  21.648 23.027 21.672 23.749 ;
     RECT  19.464 23.987 19.848 25.045 ;
     RECT  18.912 25.187 20.304 25.715 ;
     RECT  13.512 25.285 14.88 26.819 ;
     RECT  11.688 25.763 13.2 26.291 ;
     RECT  16.968 26.243 18.192 27.395 ;
     RECT  2.712 26.579 2.808 27.733 ;
     RECT  16.968 27.395 17.064 27.925 ;
  END
END dsfd_rly_276_EW
END LIBRARY
